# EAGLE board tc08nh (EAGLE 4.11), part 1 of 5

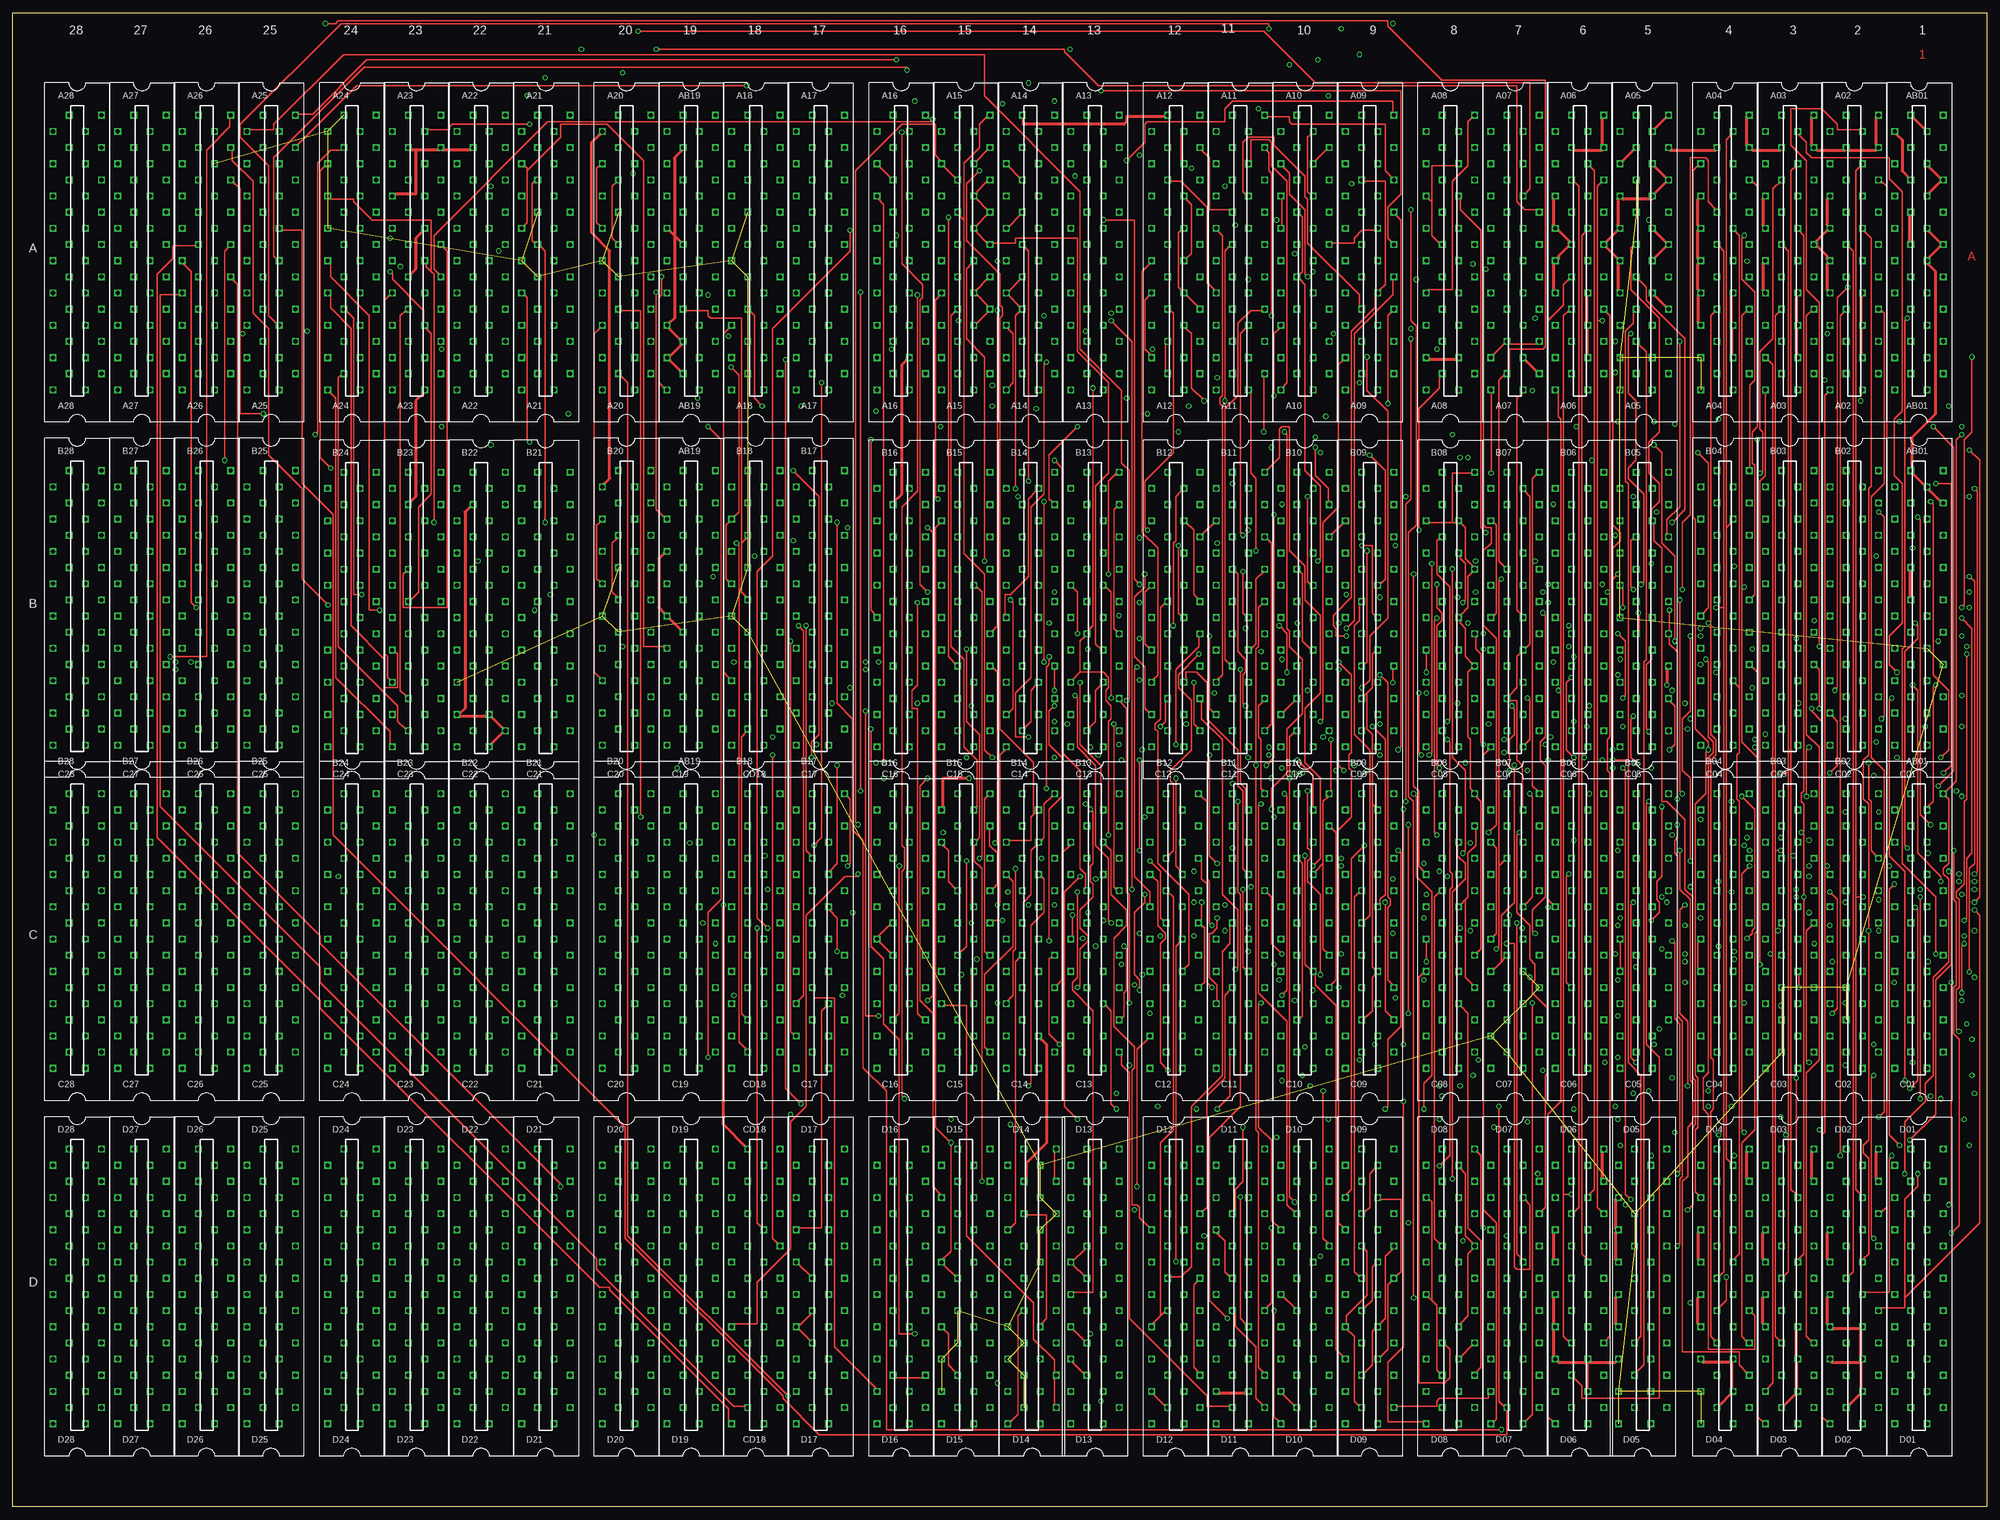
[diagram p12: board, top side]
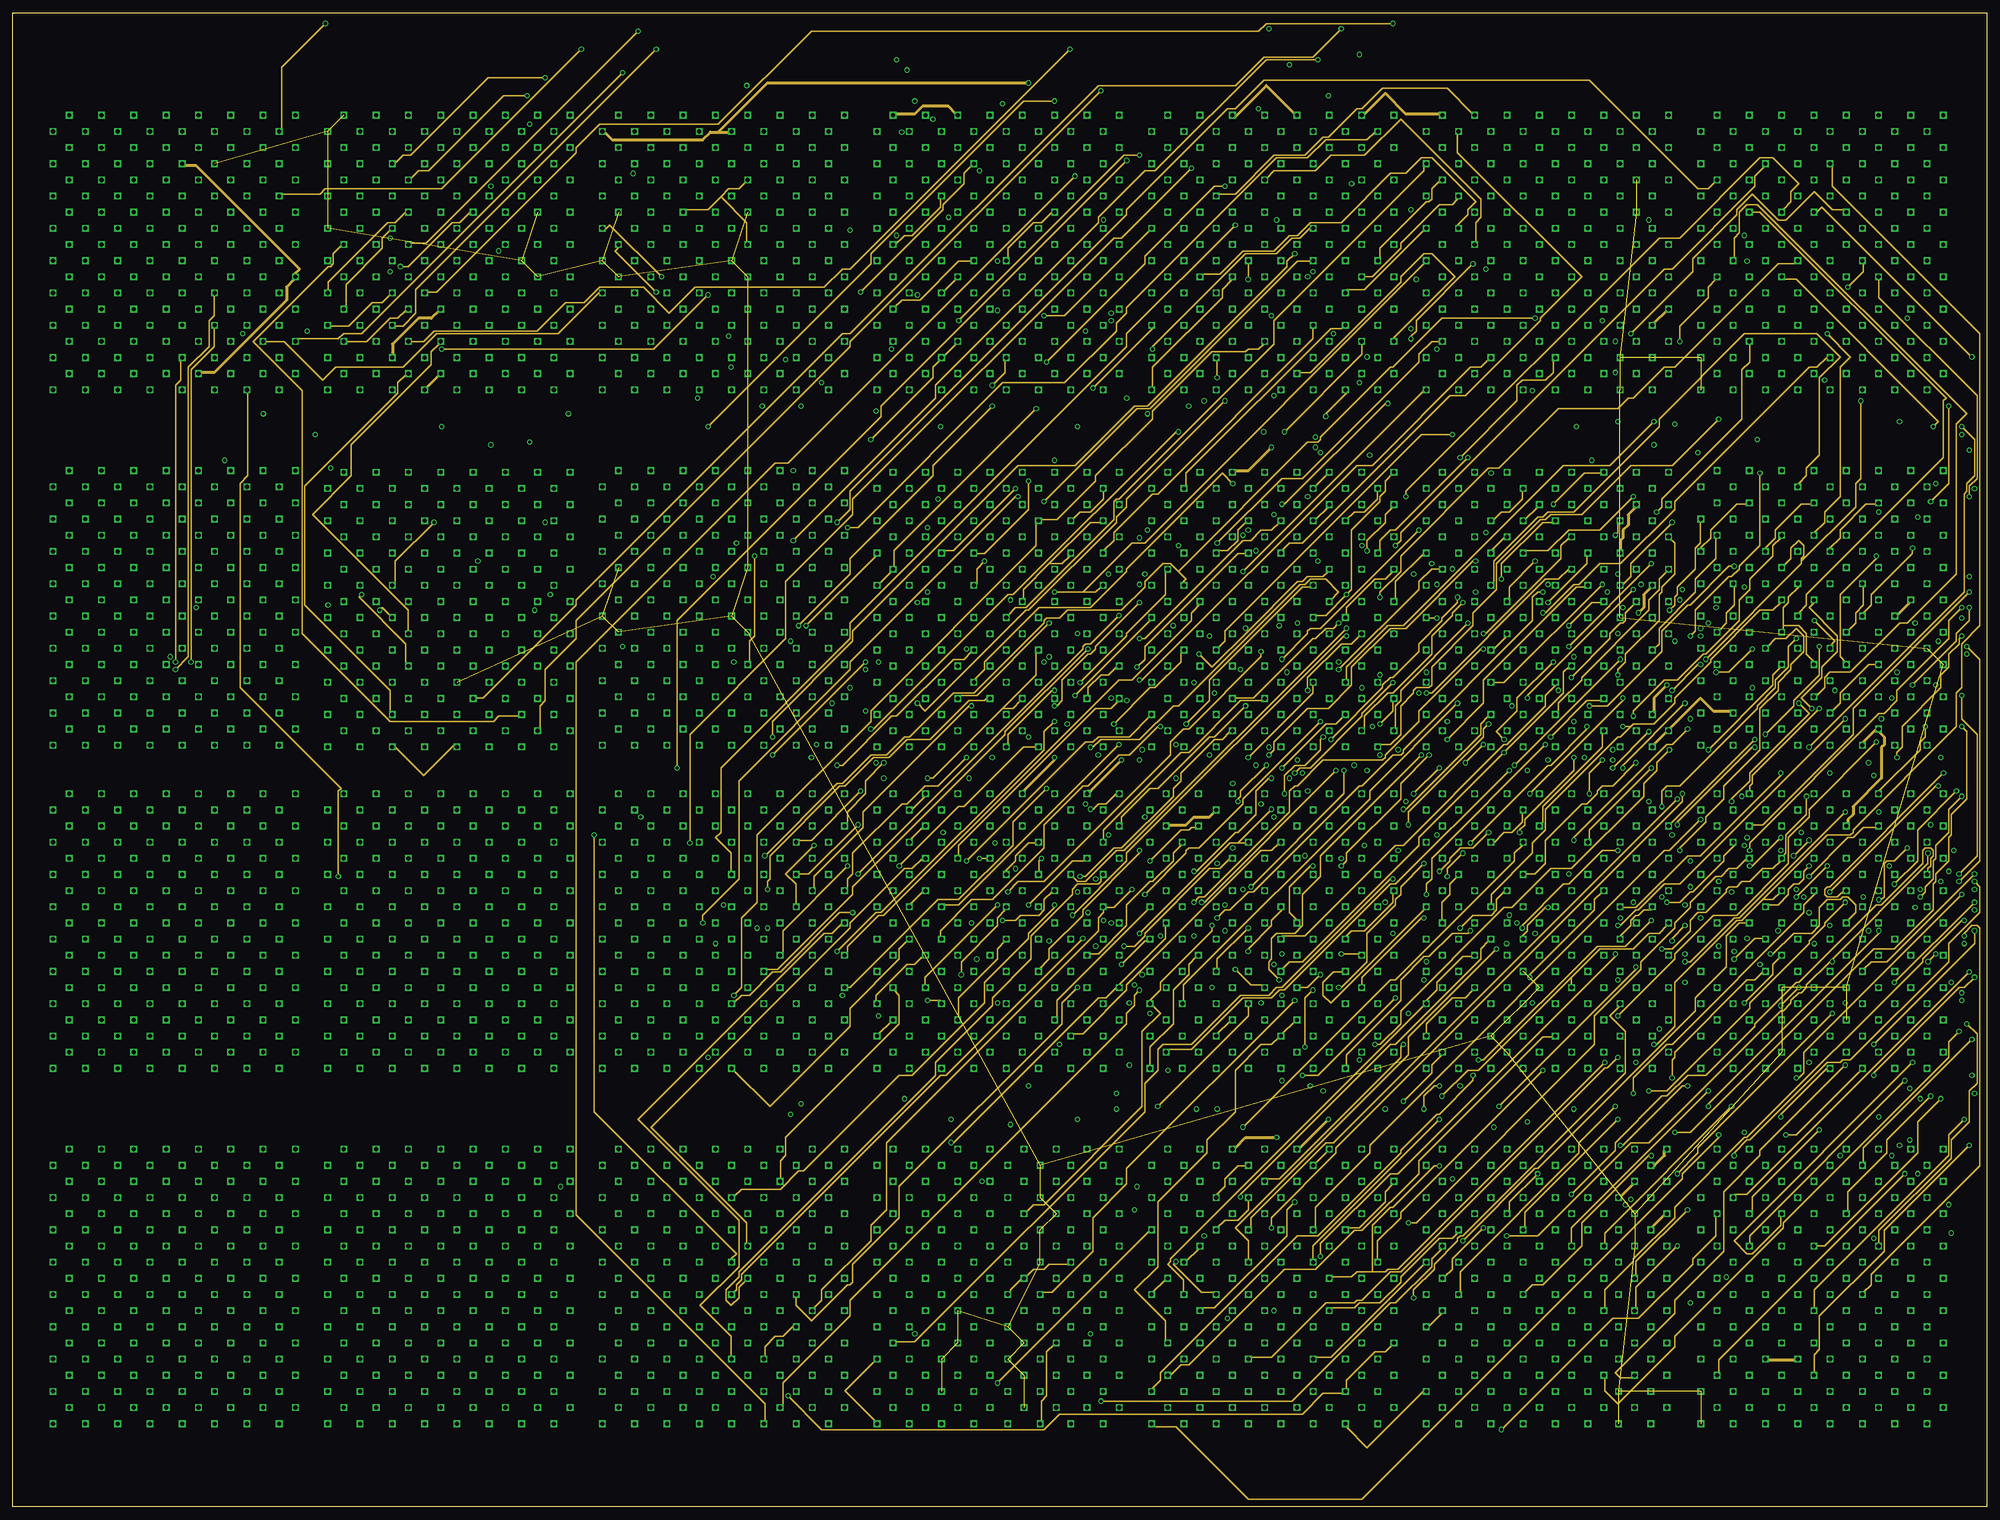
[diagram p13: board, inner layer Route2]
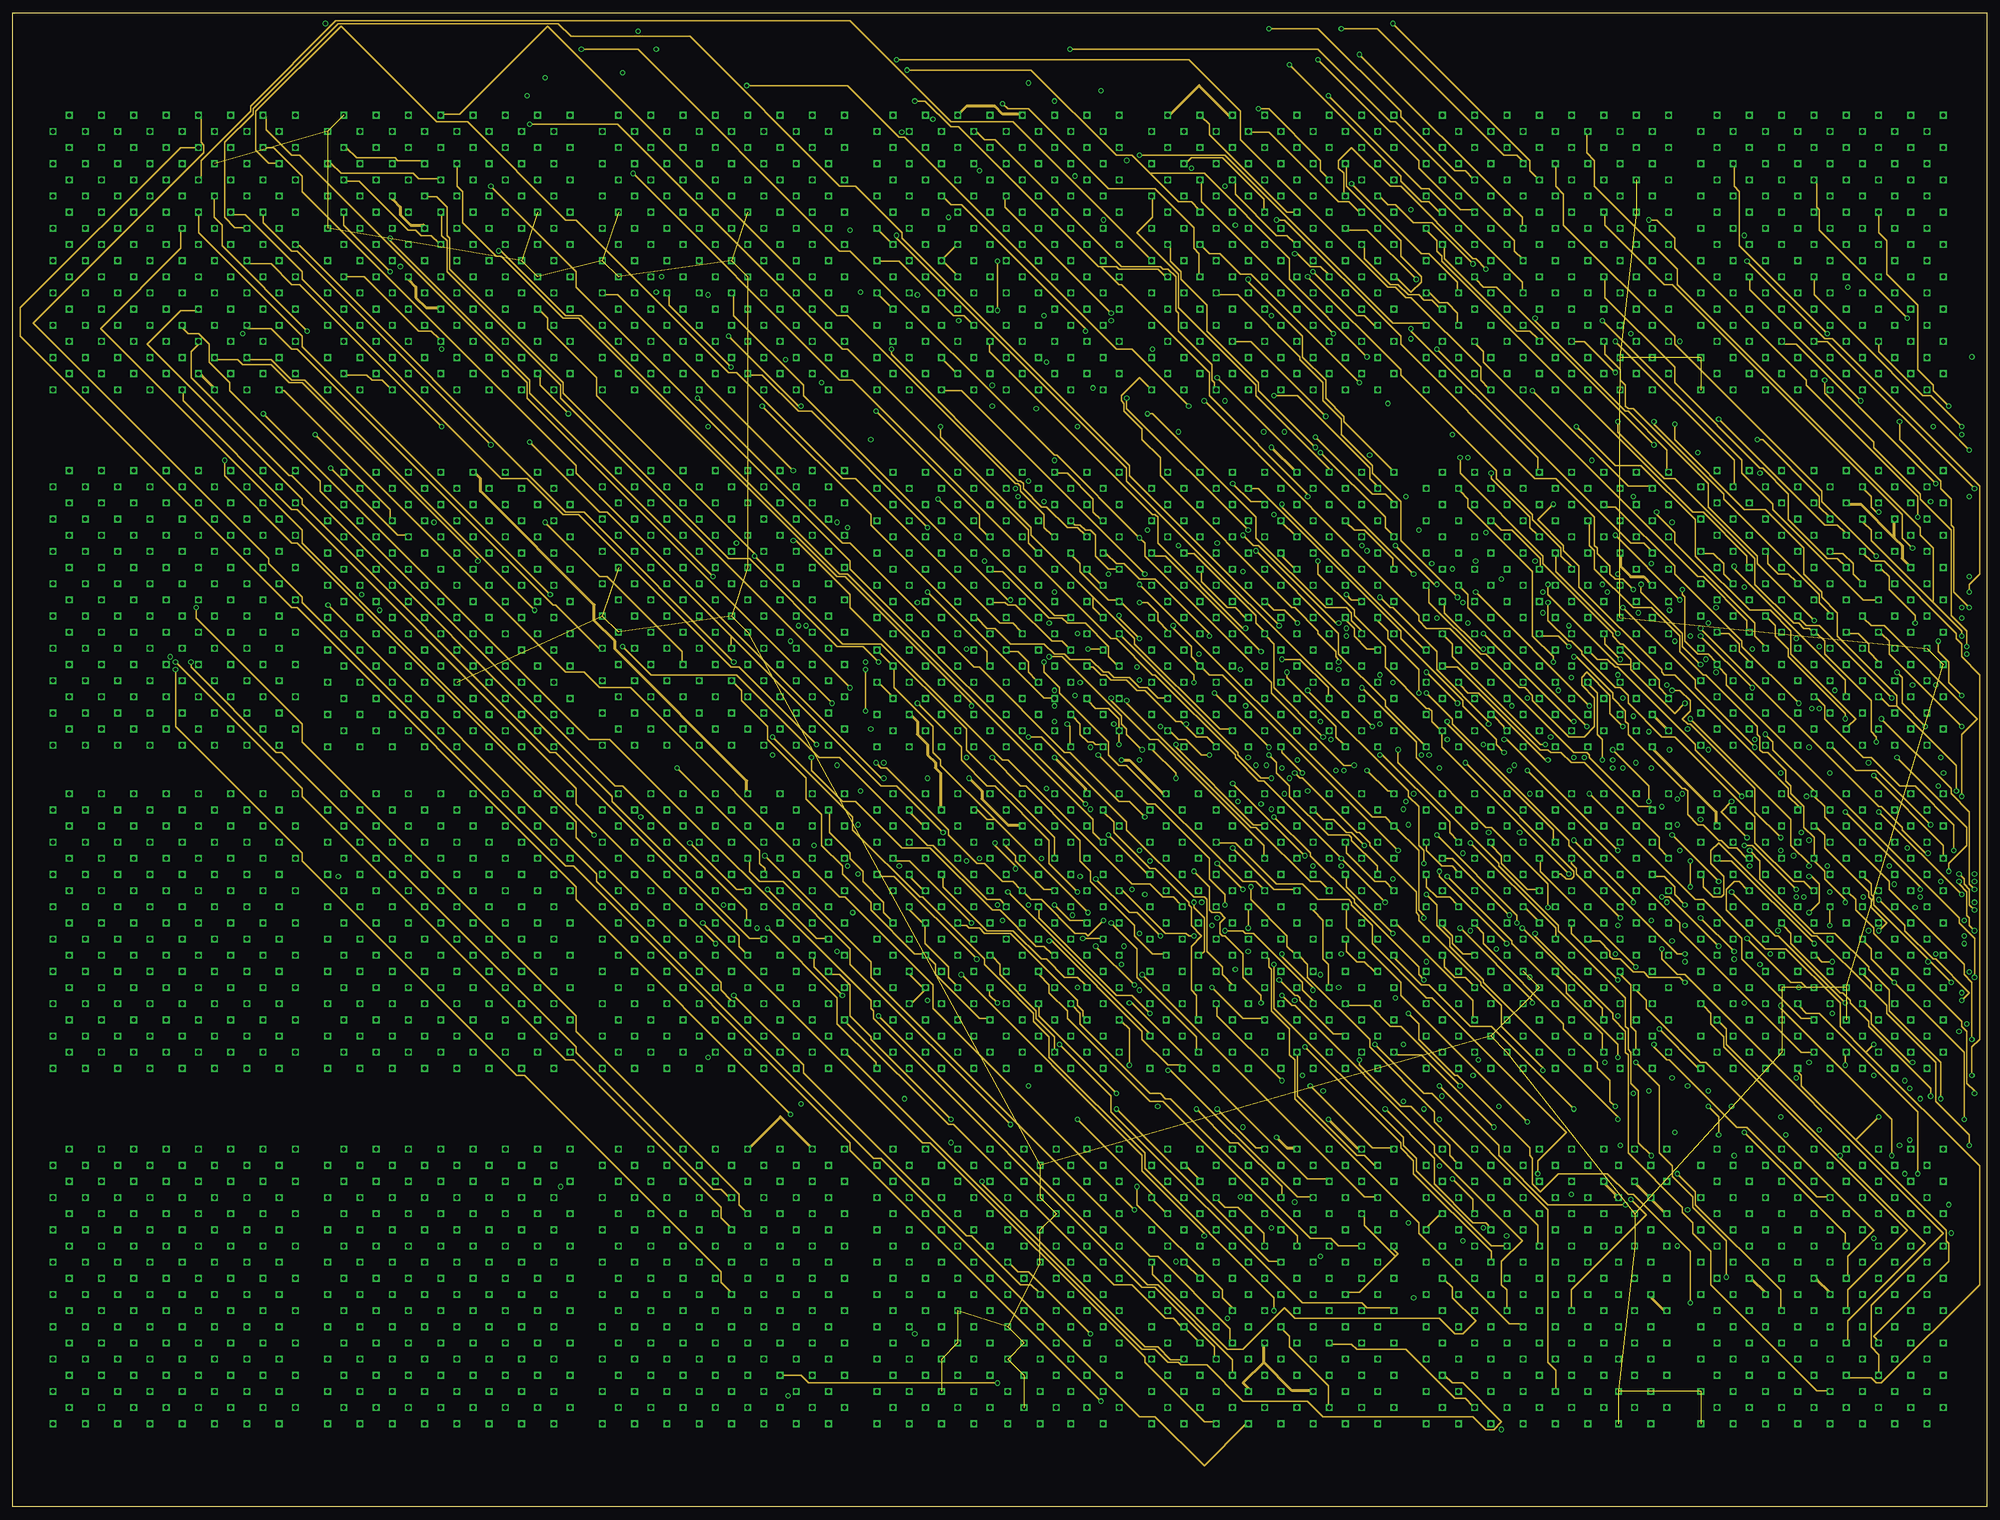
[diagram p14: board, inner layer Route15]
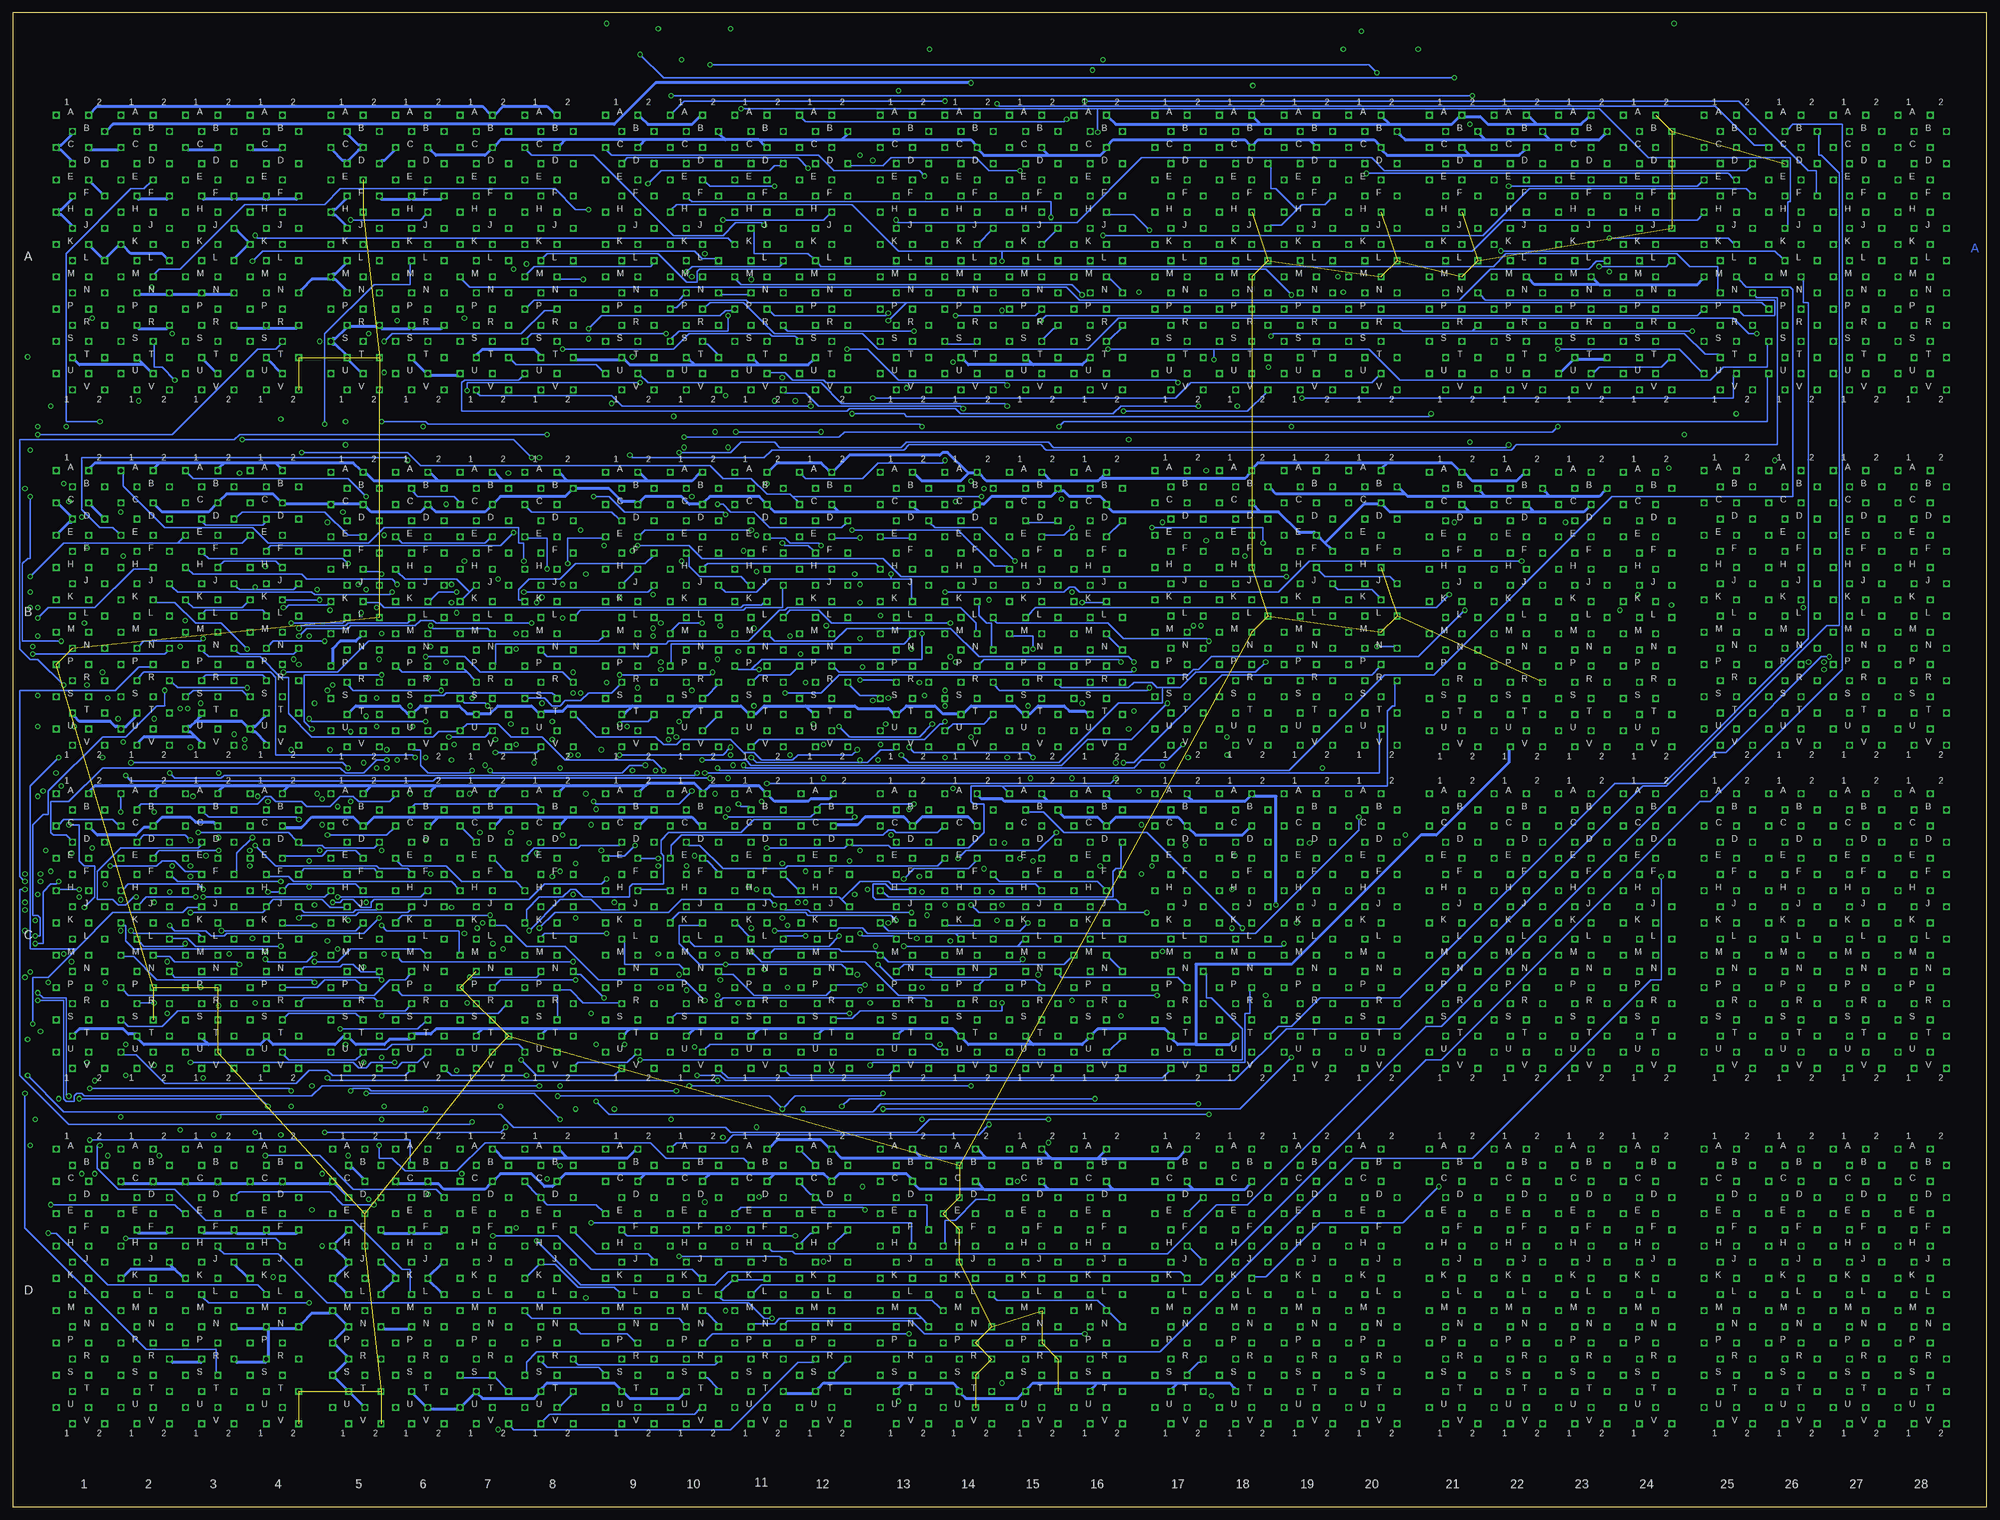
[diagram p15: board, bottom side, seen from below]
Size 387.97 x 293.68 mm. Coordinates in mm from the lower left corner, seen from the top.
Outline: 387.97,0 0,0 0,293.68 387.97,293.68 387.97,0
Copper layers (1*16): Top 0.035mm / dielectric 1.5mm / Bottom 0.035mm
Design rules "10mils": minimum track width 10mil, minimum drill 24mil, track to track 10mil, track to pad 10mil, pad to pad 10mil, via to via 10mil, smd to smd 10mil, copper to edge 40mil, drill to drill 10mil, minimum pad ring 10mil, minimum via ring 8mil, stop-mask expansion 0mil, vias tented up to drill 0mil, thermal gap 10mil
Net classes: 1 Power: width 0.635 mm, drill 0.381 mm, clearance 0.381 mm

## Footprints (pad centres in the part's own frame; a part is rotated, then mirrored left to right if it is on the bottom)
H807 = drill 0.813 square: A1 4.763,28.575; A2 -1.587,28.575; B1 1.587,25.4; B2 -4.763,25.4; C1 4.763,22.225; C2 -1.587,22.225; D1 1.587,19.05; D2 -4.763,19.05; E1 4.763,15.875; E2 -1.587,15.875; F1 1.587,12.7; F2 -4.763,12.7; H1 4.763,9.525; H2 -1.587,9.525; J1 1.587,6.35; J2 -4.763,6.35; K1 4.763,3.175; K2 -1.587,3.175; L1 1.587,0; L2 -4.763,0; M1 4.763,-3.175; M2 -1.587,-3.175; N1 1.587,-6.35; N2 -4.763,-6.35; P1 4.763,-9.525; P2 -1.587,-9.525; R1 1.587,-12.7; R2 -4.763,-12.7; S1 4.763,-15.875; S2 -1.587,-15.875; T1 1.587,-19.05; T2 -4.763,-19.05; U1 4.763,-22.225; U2 -1.587,-22.225; V1 1.587,-25.4; V2 -4.763,-25.4
H807-2 = drill 0.813 square: AA1 4.763,60.325; AA2 -1.587,60.325; AB1 1.587,57.15; AB2 -4.763,57.15; AC1 4.763,53.975; AC2 -1.587,53.975; AD1 1.587,50.8; AD2 -4.763,50.8; AE1 4.763,47.625; AE2 -1.587,47.625; AF1 1.587,44.45; AF2 -4.763,44.45; AH1 4.763,41.275; AH2 -1.587,41.275; AJ1 1.587,38.1; AJ2 -4.763,38.1; AK1 4.763,34.925; AK2 -1.587,34.925; AL1 1.587,31.75; AL2 -4.763,31.75; AM1 4.763,28.575; AM2 -1.587,28.575; AN1 1.587,25.4; AN2 -4.763,25.4; AP1 4.763,22.225; AP2 -1.587,22.225; AR1 1.587,19.05; AR2 -4.763,19.05; AS1 4.763,15.875; AS2 -1.587,15.875; AT1 1.587,12.7; AT2 -4.763,12.7; AU1 4.763,9.525; AU2 -1.587,9.525; AV1 1.587,6.35; AV2 -4.763,6.35; BA1 4.763,-9.525; BA2 -1.587,-9.525; BB1 1.587,-12.7; BB2 -4.763,-12.7; BC1 4.763,-15.875; BC2 -1.587,-15.875; BD1 1.587,-19.05; BD2 -4.763,-19.05; BE1 4.763,-22.225; BE2 -1.587,-22.225; BF1 1.587,-25.4; BF2 -4.763,-25.4; BH1 4.763,-28.575; BH2 -1.587,-28.575; BJ1 1.587,-31.75; BJ2 -4.763,-31.75; BK1 4.763,-34.925; BK2 -1.587,-34.925; BL1 1.587,-38.1; BL2 -4.763,-38.1; BM1 4.763,-41.275; BM2 -1.587,-41.275; BN1 1.587,-44.45; BN2 -4.763,-44.45; BP1 4.763,-47.625; BP2 -1.587,-47.625; BR1 1.587,-50.8; BR2 -4.763,-50.8; BS1 4.763,-53.975; BS2 -1.587,-53.975; BT1 1.587,-57.15; BT2 -4.763,-57.15; BU1 4.763,-60.325; BU2 -1.587,-60.325; BV1 1.587,-63.5; BV2 -4.763,-63.5

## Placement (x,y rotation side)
A02  M903  [H807]  361.94,244.94 0 top
A03  M903  [H807]  349.24,244.94 0 top
A04  M903  [H807]  336.54,244.94 0 top
A05  M903  [H807]  320.66,244.94 0 top
A06  M903  [H807]  307.96,244.94 0 top
A07  A07  [H807]  295.26,244.94 0 top
A08  M206X  [H807]  282.56,244.94 0 top
A09  [H807]  266.69,244.94 0 top
A10  [H807]  253.99,244.94 0 top
A11  A11  [H807]  241.29,244.94 0 top
A12  A12  [H807]  228.59,244.94 0 top
A13  H807  [H807]  212.71,244.94 0 top
A14  [H807]  200.01,244.94 0 top
A15  [H807]  187.31,244.94 0 top
A16  [H807]  174.61,244.94 0 top
A17  H807  [H807]  158.74,244.94 0 top
A18  [H807]  146.04,244.94 0 top
A20  [H807]  120.64,244.94 0 top
A21  [H807]  104.76,244.94 0 top
A22  [H807]  92.06,244.94 0 top
A23  [H807]  79.36,244.94 0 top
A24  W023  [H807]  66.66,244.94 0 top
A25  M916  [H807]  50.78,244.94 0 top
A26  M916  [H807]  38.09,244.94 0 top
A27  H807  [H807]  25.38,244.94 0 top
A28  H807  [H807]  12.68,244.94 0 top
AB01  [H807-2]  374.63,213.19 0 top
AB19  [H807-2]  133.34,213.19 0 top
B02  [H807]  361.94,175.09 0 top
B03  [H807]  349.24,175.09 0 top
B04  [H807]  336.54,175.09 0 top
B05  [H807]  320.66,174.78 0 top
B06  B06  [H807]  307.96,174.78 0 top
B07  B07  [H807]  295.26,174.78 0 top
B08  B08  [H807]  282.56,174.78 0 top
B09  M206X  [H807]  266.69,174.78 0 top
B10  B10  [H807]  253.99,174.78 0 top
B11  [H807]  241.29,174.78 0 top
B12  [H807]  228.59,174.78 0 top
B13  M206X  [H807]  212.71,174.78 0 top
B14  M206X  [H807]  200.01,174.78 0 top
B15  [H807]  187.31,174.78 0 top
B16  [H807]  174.61,174.78 0 top
B17  H807  [H807]  158.74,175.09 0 top
B18  [H807]  146.04,175.09 0 top
B20  [H807]  120.64,175.09 0 top
B21  [H807]  104.76,174.78 0 top
B22  [H807]  92.06,174.78 0 top
B23  [H807]  79.36,174.78 0 top
B24  H807  [H807]  66.66,174.78 0 top
B25  H807  [H807]  50.78,175.09 0 top
B26  H807  [H807]  38.09,175.09 0 top
B27  H807  [H807]  25.38,175.09 0 top
B28  H807  [H807]  12.68,175.09 0 top
C01  C01  [H807]  374.63,111.59 0 top
C02  [H807]  361.94,111.59 0 top
C03  [H807]  349.24,111.59 0 top
C04  C04  [H807]  336.54,111.59 0 top
C05  C05  [H807]  320.66,111.59 0 top
C06  C06  [H807]  307.96,111.59 0 top
C07  B07  [H807]  295.26,111.59 0 top
C08  C08  [H807]  282.56,111.59 0 top
C09  M206X  [H807]  266.69,111.59 0 top
C10  [H807]  253.99,111.59 0 top
C11  [H807]  241.29,111.59 0 top
C12  [H807]  228.27,111.59 0 top
C13  [H807]  212.71,111.59 0 top
C14  M206X  [H807]  200.01,111.59 0 top
C15  [H807]  187.31,111.59 0 top
C16  C16  [H807]  174.61,111.59 0 top
C17  C17  [H807]  158.74,111.59 0 top
C19  H807  [H807]  133.34,111.59 0 top
C20  H807  [H807]  120.64,111.59 0 top
C21  H807  [H807]  104.76,111.59 0 top
C22  H807  [H807]  92.06,111.59 0 top
C23  H807  [H807]  79.36,111.59 0 top
C24  H807  [H807]  66.66,111.59 0 top
C25  H807  [H807]  50.78,111.59 0 top
C26  H807  [H807]  38.09,111.59 0 top
C27  H807  [H807]  25.38,111.59 0 top
C28  H807  [H807]  12.68,111.59 0 top
CD18  [H807-2]  146.04,79.84 0 top
D01  H807  [H807]  374.63,41.74 0 top
D02  M903  [H807]  361.94,41.74 0 top
D03  M903  [H807]  349.24,41.74 0 top
D04  M903  [H807]  336.54,41.74 0 top
D05  M903  [H807]  320.34,41.74 0 top
D06  M903  [H807]  307.96,41.74 0 top
D07  D07  [H807]  295.26,41.74 0 top
D08  [H807]  282.56,41.74 0 top
D09  [H807]  266.69,41.74 0 top
D10  [H807]  253.99,41.74 0 top
D11  M206X  [H807]  241.29,41.74 0 top
D12  D12  [H807]  228.59,41.74 0 top
D13  D13  [H807]  212.71,41.74 0 top
D14  [H807]  200.33,41.74 0 top
D15  [H807]  187.31,41.74 0 top
D16  [H807]  174.61,41.74 0 top
D17  D17  [H807]  158.74,41.74 0 top
D19  H807  [H807]  133.34,41.74 0 top
D20  H807  [H807]  120.64,41.74 0 top
D21  H807  [H807]  104.76,41.74 0 top
D22  H807  [H807]  92.06,41.74 0 top
D23  H807  [H807]  79.36,41.74 0 top
D24  H807  [H807]  66.66,41.74 0 top
D25  H807  [H807]  50.78,41.74 0 top
D26  H807  [H807]  38.09,41.74 0 top
D27  H807  [H807]  25.38,41.74 0 top
D28  H807  [H807]  12.68,41.74 0 top

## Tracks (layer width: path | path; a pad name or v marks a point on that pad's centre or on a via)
00\  (via drill 0.61)
  Route2 0.254: v261.1,290.54 255.51,284.95 245.86,284.95 240.27,279.36 213.35,279.36 164.58,230.59 163.05,230.59 110.73,178.27 110.73,177.25 92.44,158.97 90.92,158.97 B22.S2
  Route15 0.254: v261.1,290.54 268.21,290.54 293.1,265.65 295.64,265.65 296.66,264.63 A07.D1
0_TO_AC\
  Route2 0.254: B06.T2 303.77,155.92 303.77,157.95 308.34,162.52 308.34,163.03 321.55,176.24 321.55,178.27 323.58,180.3 323.58,182.33 325.11,183.86 B05.H1
0_TO_DTB  (via drill 0.61)
  Top 0.254: v175.25,80.23 174.74,80.73 174.74,124.93 175.25,125.44 175.25,129.5 174.74,130.01 174.74,196.56 177.79,199.61 v177.79,238.21
  Route2 0.254: v225.03,78.7 242.81,96.48 242.81,98.51 C11.R1
  Bottom 0.254: v225.03,78.7 223.51,80.23 v175.25,80.23 | v177.79,238.21 179.82,240.25 244.84,240.25 245.86,241.26 A11.M1
0_TO_DTB\  (via drill 0.61)
  Top 0.254: 266.69,144.74 266.69,148.81 263.64,151.85 263.64,173.19 264.65,174.21 264.65,177.76 B09.K2 | 266.69,144.74 266.69,116.29 265.67,115.28 C09.K2 | 266.69,144.74 v266.18,144.74
  Route2 0.254: B10.L1 256.02,175.22 258.05,175.22 v262.11,179.29 263.13,180.3 263.13,191.99 268.72,197.57 268.72,198.59 269.73,199.61 269.73,201.64 271.26,203.16 B09.A1 | v242.81,241.26 242.81,244.31 A11.L1
  Route15 0.254: v266.18,144.74 270.24,140.68 271.26,140.68 C09.A1 | v242.81,241.26 242.81,240.75 253.48,230.09 253.48,226.02 258.05,221.45 258.05,217.89 261.61,214.34 261.61,213.32 271.26,203.67 B09.A1 | v262.11,179.29 263.13,178.27 264.65,178.27 B09.K2
0_TO_EF
  Route15 0.254: A11.E2 240.27,260.57 240.27,258.03 248.4,249.9 250.43,249.9 251.95,248.37 A10.K2
0_TO_EF\
  Top 0.254: A08.N2 278.37,239.23 282.94,239.23 282.94,260.57 285.99,263.61 285.99,272.25 287,273.27 A08.A1
  Route2 0.254: A11.F2 236.71,258.03 240.27,258.03 247.89,265.65 253.99,265.65 257.54,269.2 258.56,269.2 264.15,274.79 265.16,274.79 269.23,278.85 281.93,278.85 287,273.77 A08.A1
  Route15 0.254: A08.R1 283.96,232.63 283.96,234.66 281.93,236.69 280.4,236.69 278.37,238.72 A08.N2
0_TO_LPB\  (via drill 0.61)
  Top 0.254: v289.04,54.83 288.53,55.33 288.53,69.05 287.51,70.07 D08.A1
  Route2 0.254: v289.04,54.83 282.94,48.73 282.94,46.7 281.42,45.17 D08.K2
  Route15 0.254: D12.J2 224.01,47.71 224.01,45.68 238.75,30.95 241.79,30.95 249.92,39.08 251.95,37.05 280.4,37.05 283.45,34 284.97,34 287.51,36.54 282.94,41.11 282.94,43.14 281.42,44.67 D08.K2
0_TO_STA
  Bottom 0.254: A11.N1 243.32,238.21 248.91,238.21 A10.N2
0_TO_STA\  (via drill 0.61)
  Top 0.254: 298.69,185.89 298.69,202.15 299.71,203.16 B07.A1 | 298.69,185.89 298.69,141.69 299.71,140.68 C07.A1 | 298.69,185.89 v299.2,185.89 | B11.P2 239.25,165.57 238.24,166.59 238.24,215.86 240.78,218.4 240.78,232.63 243.32,235.17 245.86,235.17 A11.P1
  Route2 0.254: v299.2,185.89 294.12,180.81 294.12,178.27 B07.K2
  Route15 0.254: v274.81,231.61 274.81,231.1 299.71,206.21 299.71,203.67 B07.A1
  Bottom 0.254: v274.81,231.61 272.27,234.15 248.91,234.15 247.89,235.17 246.37,235.17 A11.P1
0_TO_STATE\
  Route2 0.254: CD18.AV2 141.72,85.81 148.83,78.7 164.58,94.45 164.58,98.01 174.23,107.66 174.23,109.69 175.75,111.21 C16.L1
0_TO_W\
  Route2 0.254: CD18.BH2 144.26,51.78 144.26,55.84 125.46,74.64 164.58,113.75 164.58,114.77 175.25,125.44 176.77,125.44 178.8,127.47 C16.E1
01\  (via drill 0.61)
  Route2 0.254: v271.26,291.55 246.37,291.55 244.84,290.03 156.96,290.03 138.67,271.74 115.3,271.74 110.73,267.17 110.73,266.15 83.3,238.72 81.27,238.72 A23.N1
  Route15 0.254: v271.26,291.55 298.18,264.63 298.18,262.6 299.71,261.07 A07.E1
1_TO_DF  (via drill 0.61)
  Top 0.254: C12.J1 229.6,117.31 229.6,112.23 C12.L1 229.6,111.21 228.59,110.2 v228.59,48.22
  Route2 0.254: v228.59,48.22 228.08,47.71 233.67,42.13 236.21,42.13 D11.L2 | v256.53,284.44 246.37,284.44 224.52,262.6 222.49,262.6 213.35,253.45 213.35,252.44 181.34,220.43 181.34,217.89 v153.4,189.95
  Route15 0.254: v256.53,284.44 276.34,264.63 276.34,263.11 284.47,254.98 287,254.98 A08.H1 | v153.4,189.95 153.91,189.95 164.58,179.29 164.58,176.75 194.55,146.77 195.57,146.77 219.95,122.39 223.51,122.39 226.05,119.85 228.08,119.85 229.6,118.33 C12.J1
1_TO_DTF  (via drill 0.61)
  Top 0.254: v170.17,96.48 167.62,96.48 v167.62,156.43
  Route15 0.254: v170.17,96.48 223,43.65 225.03,43.65 239.76,28.92 239.76,26.38 D11.S2 | v167.62,156.43 v167.62,164.55
  Bottom 0.254: v167.62,164.55 168.13,164.05 225.54,164.05 226.55,165.06 B12.P2
02\  (via drill 0.61)
  Route2 0.254: v104.63,280.89 93.46,280.89 78.22,265.65 76.69,265.65 75.17,264.12 A23.D2
  Route15 0.254: v264.65,285.46 296.66,253.45 296.66,251.93 A07.J1
  Bottom 0.254: v264.65,285.46 260.08,280.89 v104.63,280.89
03\  (via drill 0.61)
  Route2 0.254: v101.08,277.33 96.5,277.33 81.77,262.6 79.74,262.6 78.22,261.07 A23.E2
  Route15 0.254: v258.56,277.33 276.85,259.04 278.37,259.04 296.66,240.75 296.66,239.23 A07.N1
  Bottom 0.254: v258.56,277.33 v101.08,277.33
04\  (via drill 0.61)
  Top 0.254: v122.92,290.03 245.86,290.03 256.02,279.87 298.18,279.87 298.18,259.04 297.17,258.03 A07.F1
  Route2 0.254: v122.92,290.03 81.27,248.37 78.22,248.37 A23.K2
05\
  Bottom 0.254: A07.M1 299.71,241.26 298.18,239.74 180.83,239.74 178.29,237.2 103.62,237.2 97.52,243.29 78.22,243.29 76.69,244.82 75.17,244.82 A23.L2
06\  (via drill 0.61)
  Top 0.254: v126.48,286.47 206.74,286.47 206.74,285.97 213.35,279.36 295.64,279.36 295.64,256.5 297.17,254.98 299.71,254.98 A07.H1
  Route2 0.254: v126.48,286.47 79.23,239.23 79.23,234.66 76.69,232.12 75.17,232.12 A23.R2
07\  (via drill 0.61)
  Route2 0.254: v207.76,286.47 164.58,243.29 163.05,243.29 159.5,239.74 134.1,239.74 129.02,234.66 123.94,239.74 115.3,239.74 112.25,236.69 108.7,236.69 103.11,231.1 82.79,231.1 80.76,229.07 78.22,229.07 A23.S2
  Route15 0.254: v207.76,286.47 256.53,286.47 270.75,272.25 271.76,272.25 295.13,248.88 295.13,246.85 296.66,245.33 A07.L1
76  (via drill 0.61)
  Route15 0.254: v323.58,93.94 331.2,86.32 C04.V2
  Bottom 0.254: v323.58,93.94 308.34,93.94 306.82,95.47 C06.S2
76+77  (via drill 0.61)
  Route2 0.254: v335.26,73.11 335.26,72.61 328.15,65.49 328.15,64.48 265.16,1.49 242.81,1.49 228.59,15.71 224.01,15.71 D12.V2 | v333.23,78.7 333.23,79.21 366.76,112.74 v366.76,113.25
  Route15 0.254: v335.26,73.11 335.26,76.67 v333.23,78.7 | v366.76,113.25 368.29,114.77 365.24,117.82 365.24,119.34 364.73,119.85 364.73,120.87 356.09,129.5 356.09,132.04 354.57,133.57 C03.C1
76\
  Route2 0.254: C06.T2 302.75,92.42 300.72,92.42 276.34,68.03 276.34,65.49 265.16,54.32 263.64,54.32 256.02,46.7 249.92,46.7 231.12,27.9 229.6,27.9 227.57,25.87 D12.S2
  Bottom 0.254: D12.S2 226.55,26.38 224.52,28.41 224.01,28.41 D12.R2
77
  Bottom 0.254: C06.U2 306.82,88.86 308.34,87.34 311.39,87.34 312.41,86.32 315.45,86.32 C05.V2
77\  (via drill 0.61)
  Top 0.254: D12.T2 224.01,22.31 226.55,19.77 D12.U2
  Route2 0.254: v287,84.8 287,83.78 280.4,77.18 279.89,77.18 272.78,70.07 272.78,69.56 256.53,53.3 252.46,53.3 225.54,26.38 225.54,24.85 224.01,23.33 D12.T2
  Bottom 0.254: v287,84.8 301.74,84.8 302.75,85.81 C06.V2
+3V@A09U1  (via drill 0.61)
  Top 0.254: 278.88,256.5 278.88,249.9 280.4,248.37 A08.K2 | 278.88,256.5 278.37,257.01 A08.F2 | 278.88,256.5 278.88,263.61 283.96,263.61 A08.D1 | B13.U2 211.31,152.87 212.84,154.39 212.84,160.49 213.85,161.51 B13.R1 | A07.T2 291.07,226.53 293.1,228.56 A07.S2 294.12,228.56 299.71,228.56 A07.S1
  Route2 0.254: v221.47,162.52 221.98,162.52 264.15,204.69 267.19,204.69 286.5,223.99 288.53,223.99 290.05,225.51 A07.T2
  Route15 0.254: A08.K2 281.42,247.87 281.42,245.33 295.64,231.1 298.18,231.1 299.71,229.58 A07.S1
  Bottom 0.254: A09.U1 271.76,222.97 273.29,224.5 289.04,224.5 290.05,225.51 A07.T2 | v221.47,162.52 214.87,162.52 B13.R1
+3V@B12U1  (via drill 0.61)
  Top 0.254: B14.U2 198.61,152.87 200.14,154.39 200.14,160.49 201.15,161.51 B14.R1 | v232.14,162.01 232.14,153.89 233.16,152.87 B12.U1
  Route2 0.254: 203.69,185.38 198.61,180.3 198.61,178.27 B14.K2 | 203.69,185.38 206.23,185.38 207.76,186.91 B13.F2 | 203.69,185.38 211.82,193.51 213.85,193.51 B13.D1
  Route15 0.254: B14.N2 195.57,168.11 197.6,168.11 199.63,166.08 199.63,164.05 201.15,162.52 B14.R1 | B13.F2 208.27,186.91 209.79,185.38 209.79,183.86 215.38,178.27 216.9,178.27 B13.K1 217.92,177.76 232.14,163.54 v232.14,162.01 | B14.A1 205.22,203.16 207.25,203.16 212.33,198.08 212.33,195.54 213.85,194.02 B13.D1
  Bottom 0.254: B14.N2 195.57,168.62 195.57,173.7 196.58,173.7 198.11,175.22 198.11,177.76 B14.K2
+3V@C08U1  (via drill 0.61)
  Top 0.254: C04.N2 331.2,105.63 331.2,111.21 C04.L2 | C05.N2 315.96,105.63 315.96,111.21 C05.L2
  Route2 0.254: C05.J1 322.06,117.31 320.53,117.31 319.52,116.29 319.01,116.29 317.99,115.28 317.99,114.26 315.96,112.23 C05.L2 | v353.05,123.91 360.67,131.53 361.68,131.53 363.71,133.57 366.25,133.57 C02.C1
  Route15 0.254: v353.05,123.91 353.55,123.91 355.08,122.39 355.08,118.83 v353.05,116.8 | C05.U2 319.01,89.88 319.01,93.43 317.99,94.45 317.99,102.58 315.96,104.61 C05.N2
  Bottom 0.254: C08.U1 287.51,89.88 288.53,90.89 313.42,90.89 314.44,89.88 318.5,89.88 C05.U2 319.52,88.86 320.53,87.85 333.74,87.85 334.76,88.86 C04.U2 | C02.C1 367.27,134.07 368.29,135.09 377.94,135.09 378.95,134.07 C01.C1 | C05.J1 322.56,117.82 325.61,117.82 327.14,119.34 336.79,119.34 337.81,118.33 C04.J1 338.31,117.31 338.82,116.8 v353.05,116.8 | C04.N2 331.2,105.63 330.69,106.13 323.58,106.13 323.07,106.64 321.04,106.64 319.52,105.12 316.47,105.12 C05.N2
+3V@C15U1
  Top 0.254: C15.U1 191.5,89.88 190.99,90.39 190.99,104.61 196.58,110.2 196.58,122.9 195.57,123.91 C14.F2 | C14.A1 204.2,139.66 202.68,138.14 202.68,131.53 202.17,131.03 C14.D1 201.15,130.01 200.14,128.99 200.14,120.36 198.61,118.83 198.61,115.28 C14.K2
  Route2 0.254: C14.D1 201.15,130.52 199.63,130.52 197.09,127.98 197.09,126.96 195.06,124.93 C14.F2
  Bottom 0.254: C14.K2 198.61,114.26 204.2,114.26 C14.K1 | C16.H2 173.21,121.37 174.74,122.9 194.04,122.9 195.06,123.91 C14.F2
+3V@D09U1
  Top 0.254: D09.U1 271.76,19.77 279.89,19.77 279.89,20.79 280.4,21.3 290.05,21.3 290.05,22.31 D07.T2
  Bottom 0.254: D07.T2 291.07,23.33 293.1,25.36 D07.S2 294.12,25.36 299.71,25.36 D07.S1
+3V@D10U1
  Top 0.254: D11.F2 236.71,53.81 238.24,52.29 238.24,46.19 239.25,45.17 D11.K2 | D10.M2 251.95,39.08 249.41,41.62 D10.L2
  Route2 0.254: D11.D1 242.81,60.41 242.81,58.38 240.78,56.35 238.24,56.35 236.71,54.83 D11.F2
  Route15 0.254: D10.U1 258.56,19.77 258.56,23.84 250.94,31.46 250.94,33.49 249.41,35.01 D10.N2
  Bottom 0.254: D10.N2 249.41,36.03 251.45,38.06 251.95,38.06 D10.M2 | D11.K2 240.27,44.67 245.86,44.67 D11.K1 246.37,44.67 248.91,42.13 D10.L2 248.91,41.11 248.4,40.6 207.25,40.6 205.73,39.08 D14.M1
-15V  (via drill 0.61)
  Top 0.635: AB01.AB2 370.32,269.71 371.33,268.69 371.33,262.6 372.86,261.07 AB01.AE2 | B20.B2 116.32,201.13 117.33,202.15 117.33,246.85 113.78,250.41 113.78,268.19 115.3,269.71 A20.B2
  Route2 0.635: 138.67,270.22 137.15,270.22 135.62,268.69 117.84,268.69 116.32,270.22 A20.B2 | 138.67,270.22 140.7,270.22 A18.B2 | v199.63,279.87 148.32,279.87 138.67,270.22
  Bottom 0.635: 85.84,198.59 76.19,198.59 75.17,199.61 B23.B2 | 85.84,198.59 86.85,199.61 B22.B2 | 98.54,198.59 99.55,199.61 B21.B2 | 85.84,198.59 98.54,198.59 | 114.28,199.1 113.78,198.59 98.54,198.59 | 114.28,199.1 115.3,200.11 B20.B2 | 114.28,199.1 139.69,199.1 140.7,200.11 B18.B2 | AB01.AF2 370.32,258.03 372.86,260.57 AB01.AE2 | 85.84,268.69 76.19,268.69 75.17,269.71 A23.B2 | 85.84,268.69 86.85,269.71 A22.B2 | 98.54,268.69 99.55,269.71 A21.B2 | 98.54,268.69 85.84,268.69 | 98.54,268.69 114.28,268.69 115.3,269.71 A20.B2 | v199.63,279.87 261.61,279.87 269.73,271.74 368.29,271.74 369.3,270.73 AB01.AB2
ADDR_ACC  (via drill 0.61)
  Route2 0.254: v347.46,76.67 347.46,77.18 356.6,86.32 C02.V2
  Route15 0.254: v184.39,76.16 168.64,91.91 168.64,92.42 164.58,96.48 164.58,102.58 162.55,104.61 160.51,104.61 C17.N1
  Bottom 0.254: v184.39,76.16 207.76,76.16 210.3,73.62 246.87,73.62 247.89,74.64 289.55,74.64 292.09,77.18 346.95,77.18 v347.46,76.67
ADDR_ACC\  (via drill 0.61)
  Top 0.254: v203.19,141.19 203.19,165.06 203.69,165.57 v203.69,167.09
  Route2 0.254: v203.19,141.19 196.58,134.58 196.58,130.01 185.91,119.34 181.85,119.34 164.58,102.07 164.07,102.07 C17.P1
  Route15 0.254: v203.69,167.09 206.23,167.09 217.92,155.41 217.92,153.89 218.93,152.87 218.93,151.85 v221.98,148.81
  Bottom 0.254: v221.98,148.81 223,147.79 233.67,147.79 234.68,146.77 240.78,146.77 242.3,148.3 244.33,148.3 246.87,150.84 256.53,150.84 257.54,149.82 260.08,149.82 261.61,151.35 273.29,151.35 277.35,155.41 B08.T2
B-BRK  (via drill 0.61)
  Top 0.254: v251.95,59.91 250.94,60.92 v250.94,143.22 250.94,151.35 251.95,152.36 B10.U2 | B10.S2 251.95,158.46 249.41,155.92 B10.T2
  Route2 0.254: v251.95,59.91 250.43,58.38 250.43,53.3 236.21,39.08 233.67,39.08 D12.M1
  Route15 0.254: v365.75,143.73 379.46,130.01 379.46,127.98 C01.E1
  Bottom 0.254: B10.R2 249.41,161.51 251.45,159.47 251.95,159.47 B10.S2 | v365.75,143.73 364.73,142.71 305.29,142.71 304.79,143.22 v250.94,143.22 | B10.T2 249.41,155.41 251.95,152.87 B10.U2
B-BRK\  (via drill 0.61)
  Top 0.254: v357.11,144.23 358.63,145.76 358.63,154.39 357.62,155.41 B02.T2
  Route2 0.254: B02.J1 363.71,180.81 363.71,177.25 362.19,175.73 362.19,173.7 360.67,172.17 B02.M2 | B02.C1 366.25,197.07 364.22,197.07 359.14,191.99 359.14,190.46 357.11,188.43 B02.F2 | B02.P1 366.25,165.57 364.73,165.57 359.14,159.98 359.14,157.95 357.62,156.43 B02.T2
  Route15 0.254: B02.M2 360.67,171.67 362.7,171.67 364.73,169.63 364.73,168.11 366.76,166.08 B02.P1 | B02.F2 357.62,187.41 359.65,187.41 361.68,185.38 361.68,183.35 363.21,181.83 B02.J1 | v253.48,144.23 249.41,148.3 249.41,148.81 B10.V2
  Bottom 0.254: v253.48,144.23 253.99,143.73 346.44,143.73 346.95,143.22 356.09,143.22 v357.11,144.23
B-RUN  (via drill 0.61)
  Top 0.254: v377.94,161.51 377.43,161 377.43,138.65 376.41,137.63 C01.B1
  Route2 0.254: v282.94,210.78 276.85,210.78 238.24,172.17 238.24,170.14 236.71,168.62 B11.N2
  Bottom 0.254: v377.94,161.51 383.02,166.59 384.54,166.59 386.57,168.62 386.57,209.77 344.41,209.77 343.39,210.78 v282.94,210.78
B-XSTA  (via drill 0.61)
  Top 0.254: D12.E1 233.67,57.87 234.68,58.89 234.68,80.73 238.24,84.29 238.24,100.55 239.25,101.56 C11.P2 | v203.19,225.01 202.68,224.5 202.68,199.1 200.14,196.56 200.14,163.03 197.09,159.98 197.09,151.35 v199.63,151.35
  Route2 0.254: v238.24,259.55 236.21,259.55 222.49,245.83 222.49,244.31 v203.19,225.01
  Route15 0.254: v199.63,151.35 202.17,151.35 218.93,134.58 218.93,133.06 232.14,119.85 234.17,119.85 234.68,119.34 234.68,109.18 237.73,106.13 237.73,104.61 239.76,102.58 C11.P2
  Bottom 0.254: v238.24,259.55 250.94,259.55 251.95,260.57 A10.E2
BAC_00
  Route2 0.254: B07.D1 297.17,194.02 299.71,196.56 B07.C1
  Bottom 0.254: B06.B1 309.36,199.61 308.34,198.59 301.23,198.59 300.21,197.57 B07.C1
BAC_00\  (via drill 0.61)
  Route2 0.254: v331.71,135.09 325.61,128.99 324.6,128.99 266.69,71.08 266.69,69.56 256.02,58.89 256.02,54.83 D10.F1 | v302.75,197.07 308.85,203.16 312.41,203.16 B06.A1
  Route15 0.254: v302.75,197.07 299.71,194.02 304.79,188.94 304.79,187.92 307.83,184.87 307.83,180.81 324.09,164.55 324.09,164.05 324.6,163.54 326.63,163.54 348.98,141.19 348.98,139.66 351.01,137.63 C03.B1
  Bottom 0.254: v331.71,135.09 332.22,135.6 349.49,135.6 350.5,136.61 C03.B1
BAC_01
  Route2 0.254: B07.F2 290.56,187.92 293.1,190.46 B07.E2
  Bottom 0.254: B06.E1 312.41,190.46 311.39,189.45 295.13,189.45 294.12,190.46 B07.E2
BAC_01\  (via drill 0.61)
  Top 0.254: v257.54,81.75 257.54,52.79 258.56,51.78 D10.H1
  Route2 0.254: v321.55,81.75 325.11,81.75 341.36,98.01 341.36,99.02 353.05,110.71 353.05,111.21 356.09,114.26 356.09,114.77 v360.16,118.83
  Route15 0.254: v360.16,118.83 360.16,119.34 356.09,123.41 356.09,124.93 354.06,126.96 C03.E1 354.06,127.98 354.06,131.53 352.03,133.57 352.03,137.63 349.49,140.17 349.49,141.69 348.47,142.71 348.47,144.74 344.92,148.3 343.9,148.3 343.39,148.81 343.39,151.35 342.88,151.85 342.88,153.38 332.73,163.54 332.22,163.54 327.65,168.11 327.65,171.16 322.06,176.75 318.5,176.75 310.88,184.37 310.88,187.92 309.87,188.94 309.87,193.51 B06.D1
  Bottom 0.254: v257.54,81.75 317.49,81.75 317.99,82.26 321.04,82.26 v321.55,81.75
BAC_02
  Bottom 0.254: 298.18,179.79 299.71,178.27 B07.K1 | 298.18,179.79 297.17,180.81 B07.J1 | 298.18,179.79 300.72,182.33 310.88,182.33 312.41,183.86 B06.H1
BAC_02\  (via drill 0.61)
  Route2 0.254: v280.4,76.16 255.51,51.27 255.51,48.73 D10.J1 | v318.5,81.24 318.5,84.29 325.11,90.89 326.12,90.89 352.03,116.8 352.03,118.33 354.57,120.87 C03.H1 | v301.74,177.76 309.36,185.38 309.36,186.91 B06.F1
  Route15 0.254: v301.74,177.76 301.74,174.21 305.8,170.14 306.31,170.14 308.34,168.11 308.34,167.6 314.94,161 315.96,161 317.49,159.47 317.49,157.95 324.09,151.35 326.63,151.35 342.38,135.6 342.38,130.52 350,122.9 352.03,122.9 353.55,121.37 C03.H1
  Bottom 0.254: v280.4,76.16 285.48,81.24 v318.5,81.24
BAC_03  (via drill 0.61)
  Route2 0.254: B07.N2 291.07,168.62 293.61,171.16 B07.M2 | v305.8,173.19 310.37,177.76 312.41,177.76 B06.K1
  Bottom 0.254: v305.8,173.19 305.29,172.68 294.62,172.68 294.12,172.17 B07.M2
BAC_03\  (via drill 0.61)
  Top 0.254: v353.05,87.34 352.54,87.85 352.54,113.25 353.55,114.26 C03.K1 | v281.93,150.84 282.43,150.33 282.43,124.93 282.94,124.42 282.94,121.88 282.43,121.37 282.43,69.05 v280.4,67.02
  Route2 0.254: 267.19,46.19 269.73,46.19 270.24,46.7 272.27,46.7 v312.91,87.34 | 267.19,46.19 264.15,46.19 263.13,45.17 259.06,45.17 D10.K1 | v281.93,150.84 289.04,157.95 289.04,162.52 307.32,180.81 309.36,180.81 B06.J1 | v280.4,67.02 279.38,67.02 271.26,58.89 270.75,58.89 267.19,55.33 267.19,46.19
  Bottom 0.254: v312.91,87.34 317.49,87.34 318.5,86.32 320.03,86.32 321.04,87.34 v353.05,87.34
BAC_04  (via drill 0.61)
  Top 0.254: 292.59,107.15 293.1,107.66 293.1,108.17 C07.M2 | 292.59,107.15 291.07,105.63 C07.N2 | v295.13,145.76 295.13,118.83 292.59,116.29 292.59,107.15
  Route2 0.254: v295.13,145.76 v315.96,166.59
  Route15 0.254: v315.96,166.59 312.91,169.63 312.91,171.16 B06.M1
BAC_04\  (via drill 0.61)
  Route2 0.254: v293.61,53.3 299.71,53.3 317.99,71.59 321.55,71.59 347.46,97.5 347.97,97.5 349.49,99.02 349.49,99.53 351.01,101.05 351.52,101.05 352.54,102.07 352.54,102.58 357.11,107.15 | 357.11,107.15 v357.62,107.15 | v376.41,128.49 376.41,126.45 357.11,107.15
  Route15 0.254: v357.62,107.15 355.59,107.15 354.57,108.17 C03.M1 | v331.71,172.68 366.76,137.63 367.27,137.63 371.33,133.57 371.33,133.06 375.91,128.49 v376.41,128.49
  Bottom 0.254: v293.61,53.3 280.91,53.3 274.31,46.7 254.49,46.7 252.97,45.17 D10.K2 | v331.71,172.68 331.2,173.19 322.56,173.19 322.06,173.7 310.37,173.7 309.87,174.21 B06.L1
BAC_05
  Bottom 0.254: 298.69,164.05 299.71,165.06 B07.P1 | 298.69,164.05 297.17,162.52 B07.R1 | 298.69,164.05 311.39,164.05 312.41,165.06 B06.P1
BAC_05\  (via drill 0.61)
  Top 0.254: v340.85,111.72 341.87,112.74 341.87,113.25 342.38,113.75 342.38,137.12 v339.84,139.66
  Route15 0.254: v340.85,111.72 349.49,103.09 351.52,103.09 352.54,102.07 353.55,102.07 C03.P1 | v339.84,139.66 330.69,148.81 330.69,149.82 315.45,165.06 314.94,165.06 313.42,166.59 311.39,166.59 309.87,168.11 B06.N1
BAC_06  (via drill 0.61)
  Top 0.254: v273.29,90.89 v273.29,137.12
  Route2 0.254: v273.29,90.89 272.78,90.39 272.78,88.35 248.91,64.48 246.37,64.48 D11.C1 | v273.29,137.12 273.8,137.12 288.53,151.85 288.53,153.89 290.05,155.41 B07.T2 | v302.25,151.35 309.36,158.46 312.41,158.46 B06.S1
  Route15 0.254: B07.U2 293.1,152.87 293.1,153.38 291.07,155.41 B07.T2
  Bottom 0.254: v302.25,151.35 295.13,151.35 294.12,152.36 B07.U2
BAC_06\  (via drill 0.61)
  Route2 0.254: v309.87,140.17 309.87,144.23 v312.41,146.77
  Route15 0.254: v309.87,140.17 330.69,119.34 332.22,119.34 339.84,111.72 339.84,107.66 351.52,95.97 353.55,95.97 C03.S1 | v312.41,146.77 312.41,150.84 311.39,151.85 311.39,159.98 309.87,161.51 B06.R1
BAC_07  (via drill 0.61)
  Top 0.254: v241.79,74.64 241.79,63.97 240.27,62.45 240.27,57.87 D11.E2
  Route2 0.254: v241.79,74.64 270.75,103.59 271.76,103.59 295.13,126.96 295.13,128.49 296.66,130.01 C07.D1 | B06.U1 312.41,152.36 312.41,149.31 300.72,137.63 300.72,134.58 300.21,134.07 C07.C1
  Bottom 0.254: C07.C1 299.71,133.57 297.17,131.03 C07.D1
BAC_07\  (via drill 0.61)
  Route15 0.254: v297.67,144.74 327.65,114.77 327.65,113.25 351.52,89.37 353.55,89.37 C03.U1
  Bottom 0.254: v297.67,144.74 298.18,144.23 306.31,144.23 307.83,145.76 307.83,148.81 309.36,148.81 B06.V1
BAC_08  (via drill 0.61)
  Top 0.254: v291.58,109.69 292.09,110.2 292.09,125.95 | 292.09,125.95 293.1,126.96 C07.E2 | v292.59,182.33 292.09,181.83 292.09,125.95
  Route2 0.254: v291.58,109.69 274.31,92.42 274.31,88.86 240.27,54.83 242.81,52.29 242.81,48.73 D11.J1 | v292.59,182.33 292.59,185.38 300.72,193.51 302.75,193.51 B06.D2
  Bottom 0.254: C07.F2 291.07,124.93 293.1,126.96 C07.E2
BAC_08\  (via drill 0.61)
  Route2 0.254: v351.01,157.95 353.05,155.92 341.36,144.23 341.36,142.71 337.81,139.15 v337.81,138.65
  Route15 0.254: v351.01,157.95 339.84,169.13 339.84,170.14 326.63,183.35 326.63,184.87 314.94,196.56 312.91,196.56 B06.C1 | v337.81,138.65 335.77,136.61 v340.85,131.53
  Bottom 0.254: v340.85,131.53 343.9,128.49 343.9,124.93 C03.F2
BAC_09  (via drill 0.61)
  Top 0.254: v315.45,171.67 316.98,170.14 316.98,159.47 v316.47,158.97 | v298.18,140.17 298.69,139.66 298.69,119.85 297.17,118.33 C07.J1
  Route2 0.254: v316.47,158.97 316.47,158.46 v298.18,140.17
  Route15 0.254: C07.J1 297.17,117.82 299.71,115.28 C07.K1 | v315.45,171.67 303.26,183.86 303.26,186.91 B06.F2
BAC_09\  (via drill 0.61)
  Route2 0.254: v353.05,125.95 352.03,124.93 352.03,123.41 351.01,122.39 350,122.39 348.98,121.37 348.98,120.36 346.95,118.33 344.92,118.33 C03.J2 | v289.04,171.67 289.55,171.67 304.28,186.4 304.28,188.94 305.8,190.46 B06.E2
  Route15 0.254: v353.05,125.95 353.05,126.45 349.49,130.01 349.49,135.09 v329.68,154.9 | v306.82,154.39 306.31,154.39 v289.04,171.67
  Bottom 0.254: v329.68,154.9 329.17,154.39 v306.82,154.39
BAC_10\  (via drill 0.61)
  Top 0.254: v254.49,241.77 253.99,242.28 253.99,254.98 250.94,258.03 250.94,262.09 249.41,263.61 A10.D2
  Route2 0.254: v338.31,107.66 342.38,111.72 343.9,111.72 C03.L2 | v277.86,159.98 278.88,159.98 301.23,182.33 303.77,182.33 305.8,184.37 B06.H2
  Route15 0.254: v254.49,241.77 272.78,223.48 272.78,222.47 291.58,203.67 291.58,202.15 298.69,195.03 298.69,194.02 304.28,188.43 304.28,186.91 306.31,184.87 B06.H2 | v328.66,108.67 327.14,108.67 305.8,130.01 305.8,131.03 282.94,153.89 282.94,154.9 v277.86,159.98
  Bottom 0.254: v338.31,107.66 337.81,107.15 330.19,107.15 v328.66,108.67
BAC_11\  (via drill 0.61)
  Top 0.254: v236.71,115.79 236.71,113.75 235.7,112.74 235.19,112.74 235.19,104.1 236.71,102.58 236.71,99.53 C11.R2
  Route2 0.254: v326.12,84.29 326.12,87.85 326.63,88.35 326.63,89.37 340.85,103.59 342.38,103.59 343.9,105.12 C03.N2 | v300.72,179.79 299.71,179.79 298.69,178.78 298.69,174.21 273.29,148.81 273.29,148.3 272.78,147.79 271.26,147.79 265.16,141.69 264.65,141.69 243.83,120.87 242.81,120.87 239.25,117.31 238.24,117.31 v236.71,115.79
  Route15 0.254: v249.41,83.78 236.71,96.48 236.71,98.51 C11.R2
  Bottom 0.254: v249.41,83.78 325.61,83.78 v326.12,84.29 | v300.72,179.79 304.28,179.79 305.8,178.27 B06.K2
BLK_IN_SYNC  (via drill 0.61)
  Top 0.254: v218.43,110.2 218.93,109.69 218.93,101.56 218.43,101.05 218.43,96.48 217.92,95.97 C13.S1
  Route2 0.254: v218.43,110.2 220.46,110.2 222.49,112.23 222.49,112.74 235.19,125.44 237.22,125.44 239.25,127.47 C11.E2
  Route15 0.254: v219.44,86.83 219.44,93.94 217.92,95.47 C13.S1
  Bottom 0.254: v219.44,86.83 218.93,87.34 145.78,87.34 145.78,96.99 144.77,96.99 144.77,101.56 CD18.AP2
BLK_IN_SYNC\  (via drill 0.61)
  Top 0.254: v216.9,78.19 215.89,79.21 215.89,97.5 214.87,98.51 C13.R1 | v136.64,212.31 139.18,209.77 139.18,119.34 136.64,116.8 v136.64,88.35
  Route2 0.254: v204.71,276.31 198.61,276.31 168.64,246.34 168.64,244.31 v136.64,212.31
  Route15 0.254: v216.9,78.19 246.87,48.22 248.91,48.22 D10.J2
  Bottom 0.254: v204.71,276.31 256.02,276.31 258.56,273.77 A10.A1 | v136.64,88.35 146.8,78.19 v216.9,78.19
BMB_00
  Bottom 0.254: C08.B1 284.47,137.63 284.97,138.14 308.85,138.14 309.36,137.63 C06.B1
BMB_00\
  Bottom 0.254: C06.A1 312.91,139.66 313.93,138.65 320.03,138.65 321.04,139.66 323.58,139.66 325.61,137.63 330.19,137.63 331.2,138.65 336.28,138.65 337.3,139.66 338.31,139.66 339.84,138.14 362.7,138.14 363.21,137.63 C02.B1
BMB_01
  Bottom 0.254: C08.H1 287.51,121.37 289.04,122.9 299.71,122.9 302.75,125.95 311.39,125.95 312.41,126.96 C06.E1
BMB_01\  (via drill 0.61)
  Top 0.254: v364.73,146.27 364.73,139.15 365.24,138.65 365.24,128.99 366.25,127.98 C02.E1
  Route2 0.254: v322.06,145.25 309.87,133.06 309.87,131.03 C06.D1
  Bottom 0.254: v322.06,145.25 323.07,146.27 v364.73,146.27
BMB_02  (via drill 0.61)
  Route2 0.254: v298.18,104.1 298.18,104.61 310.88,117.31 310.88,119.34 312.41,120.87 C06.H1
  Bottom 0.254: v298.18,104.1 284.97,104.1 284.47,104.61 C08.N1
BMB_02\  (via drill 0.61)
  Route15 0.254: v340.35,130.01 341.87,130.01 v350.5,121.37
  Bottom 0.254: v340.35,130.01 336.28,125.95 316.47,125.95 315.96,125.44 310.37,125.44 309.87,124.93 C06.F1 | v350.5,121.37 351.52,122.39 365.24,122.39 366.25,121.37 C02.H1
BMB_03  (via drill 0.61)
  Route15 0.254: v294.12,116.29 282.94,127.47 281.42,127.47 C08.E2
  Bottom 0.254: v294.12,116.29 311.39,116.29 312.41,115.28 C06.K1
BMB_03\  (via drill 0.61)
  Route15 0.254: v331.71,115.79 v338.31,109.18
  Bottom 0.254: v331.71,115.79 331.2,116.29 320.53,116.29 320.03,116.8 310.37,116.8 309.87,117.31 C06.J1 | v338.31,109.18 338.82,109.69 364.22,109.69 365.75,111.21 365.75,114.26 366.25,114.26 C02.K1
BMB_04  (via drill 0.61)
  Top 0.254: v277.86,107.15 277.86,111.21 C08.L2
  Bottom 0.254: v277.86,107.15 311.39,107.15 312.41,108.17 C06.M1
BMB_04\  (via drill 0.61)
  Route15 0.254: v328.66,103.09 327.65,104.1 321.55,104.1 320.53,105.12 318.5,105.12 315.96,107.66 314.44,107.66 313.93,108.17 313.93,109.18 311.9,111.21 309.87,111.21 C06.L1
  Bottom 0.254: v328.66,103.09 329.17,103.59 359.65,103.59 364.22,108.17 366.25,108.17 C02.M1
BMB_05
  Bottom 0.254: C08.S2 280.91,95.97 280.91,100.55 311.39,100.55 312.41,101.56 C06.P1
BMB_05\
  Bottom 0.254: C06.N1 309.87,104.61 310.88,103.59 313.93,103.59 316.98,100.55 365.24,100.55 366.25,101.56 C02.P1
BMB_06  (via drill 0.61)
  Route2 0.254: v296.66,113.75 296.66,114.26 304.79,122.39 305.8,122.39 312.41,128.99 v315.45,128.99 | v293.1,150.84 291.58,152.36 295.64,156.43 295.64,158.97 v302.75,166.08
  Route15 0.254: v296.66,113.75 312.41,98.01 312.41,95.97 C06.S1 | v315.45,128.99 293.61,150.84 v293.1,150.84 | v302.75,166.08 302.75,167.09 298.69,171.16 298.69,183.86 285.99,196.56 285.99,198.08 284.47,199.61 B08.B1
BMB_06\
  Bottom 0.254: C06.R1 309.87,98.51 310.88,97.5 355.59,97.5 358.63,94.45 365.24,94.45 366.25,95.47 C02.S1
BMB_07  (via drill 0.61)
  Top 0.254: v284.97,128.49 285.48,128.99 285.48,144.74 282.94,147.28 v282.94,184.37
  Route2 0.254: v281.93,123.91 281.93,125.44 v284.97,128.49
  Route15 0.254: v281.93,123.91 294.62,111.21 294.62,110.71 312.41,92.93 312.41,89.88 C06.U1
  Bottom 0.254: v282.94,184.37 282.94,190.46 287,190.46 B08.E1
BMB_07\
  Bottom 0.254: C06.V1 309.87,85.81 310.88,84.8 325.11,84.8 326.12,85.81 329.68,85.81 332.22,83.27 358.12,83.27 363.71,88.86 366.25,88.86 C02.U1
BMB_08  (via drill 0.61)
  Top 0.254: v281.93,154.39 282.43,154.9 282.43,180.81 279.89,183.35 279.89,189.95 280.4,190.46 B08.E2
  Route15 0.254: v281.93,154.39 281.93,153.89 302.75,133.06 302.75,131.03 C06.D2
BMB_08\  (via drill 0.61)
  Route15 0.254: v326.12,132.04 v335.26,122.9
  Bottom 0.254: v326.12,132.04 314.44,132.04 312.91,133.57 C06.C1 | v335.26,122.9 355.59,122.9 356.6,123.91 C02.F2
BMB_09  (via drill 0.61)
  Top 0.254: v289.04,149.82 288.53,150.33 288.53,167.6 287.51,168.62 287.51,171.16 B08.M1
  Route2 0.254: v285.48,146.27 v289.04,149.82
  Route15 0.254: v285.48,146.27 306.82,124.93 306.82,123.91 306.31,123.41 305.29,123.41 304.28,124.42 303.77,124.42 C06.F2
BMB_09\  (via drill 0.61)
  Route15 0.254: v315.96,115.79 307.32,124.42 307.32,125.44 306.31,126.45 306.31,126.96 C06.E2 | v357.11,114.26 357.11,117.31 C02.J2
  Bottom 0.254: v315.96,115.79 319.01,112.74 345.93,112.74 346.44,112.23 348.98,112.23 350,113.25 356.09,113.25 v357.11,114.26
BMB_10  (via drill 0.61)
  Top 0.254: v301.74,146.77 301.74,119.34 302.75,118.33 C06.J2
  Route15 0.254: v301.74,146.77 301.23,146.77 288.02,159.98 285.99,159.98 284.47,161.51 B08.R1
BMB_10\  (via drill 0.61)
  Route15 0.254: v324.09,119.85 325.61,119.85 v335.26,110.2
  Bottom 0.254: v324.09,119.85 307.83,119.85 306.82,120.87 C06.H2 | v335.26,110.2 352.03,110.2 353.55,111.72 356.6,111.72 C02.L2
BMB_11  (via drill 0.61)
  Route2 0.254: v286.5,130.52 301.74,145.76 302.25,145.76 309.36,152.87 v309.36,153.38
  Route15 0.254: v286.5,130.52 303.26,113.75 303.26,112.23 C06.L2 | v309.36,153.38 285.99,176.75 285.99,179.29 284.47,180.81 B08.J1
BMB_11\  (via drill 0.61)
  Route15 0.254: v315.45,103.59 306.31,112.74 306.31,114.26 C06.K2
  Bottom 0.254: v315.45,103.59 315.96,104.1 356.09,104.1 356.6,104.61 C02.N2
BMB_TO_DTB
  Top 0.254: 282.94,193.51 283.96,193.51 B08.D1 284.47,193.51 285.48,192.49 285.48,186.4 287,184.87 B08.H1 287,183.86 285.99,182.84 285.99,176.75 284.47,175.22 B08.L1 284.47,174.21 284.47,173.7 285.48,172.68 285.48,167.09 287,165.57 B08.P1 287,165.06 285.99,164.05 285.99,151.35 286.5,150.84 286.5,141.19 287,140.68 C08.A1 287.51,139.66 288.53,138.65 288.53,109.69 287.51,108.67 C08.M1 | 282.94,193.51 278.37,193.51 B08.D2 | 282.94,193.51 282.94,203.16 287,203.16 B08.A1
  Route2 0.254: C08.K2 280.91,115.28 280.91,118.83 282.43,120.36 282.43,122.39 283.96,123.91 C08.F1 | D12.L1 230.11,42.13 230.11,44.67 227.06,47.71 227.57,48.22 227.57,48.73 277.35,98.51 C08.R2 277.86,99.53 279.89,101.56 279.89,103.09 284.97,108.17 287,108.17 C08.M1
  Route15 0.254: C08.M1 287,108.67 284.97,108.67 282.94,110.71 282.94,112.23 280.91,114.26 C08.K2 | C08.D2 277.86,130.01 277.86,128.99 280.91,125.95 282.94,125.95 283.96,124.93 C08.F1
BMR00  (via drill 0.61)
  Route15 0.254: v170.17,166.08 167.12,169.13 162.04,169.13 144.77,186.4 140.7,186.4 108.19,218.91 108.19,220.94 85.84,243.29 85.84,249.39 85.33,249.9 85.33,255.49 83.3,257.52 81.27,257.52 A23.F1
  Bottom 0.254: v170.17,166.08 170.67,166.59 197.09,166.59 198.11,165.57 B14.P2
BMR00\  (via drill 0.61)
  Route15 0.254: v164.58,161 107.68,217.89 107.68,220.43 85.33,242.79 85.33,248.88 84.31,249.9 84.31,253.96 A23.H1
  Bottom 0.254: v164.58,161 165.09,160.49 194.04,160.49 195.06,161.51 B14.R2
BMR01  (via drill 0.61)
  Top 0.254: v101.58,271.74 86.34,271.74 85.84,271.23 85.84,270.73 81.27,270.73 A23.B1
  Route15 0.254: v101.58,271.74 118.86,271.74 163.05,227.55 164.07,227.55 199.63,191.99 199.63,189.45 201.15,187.92 B14.F1
BMR01\
  Route15 0.254: A23.A1 84.31,273.77 87.87,273.77 105.14,291.05 162.04,234.15 164.07,234.15 197.09,201.13 197.6,201.13 198.11,200.62 198.11,199.61 202.68,195.03 202.68,192.49 204.2,190.97 B14.E1
C00  (via drill 0.61)
  Top 0.254: A12.L2 223.51,244.31 221.98,242.79 221.98,191.48 225.03,188.43 225.03,163.54 224.01,162.52 B12.R2 | v219.44,99.02 219.44,120.36 218.93,120.87 218.93,156.93 217.92,157.95 217.92,158.46 B13.S1
  Route2 0.254: C15.E2 185.91,127.98 185.91,130.01 212.84,156.93 215.89,156.93 217.41,158.46 B13.S1
  Route15 0.254: A26.E2 37.07,261.07 37.07,264.63 46.72,274.28 46.72,275.3 63.48,292.06 164.58,292.06 184.39,272.25 196.58,272.25 223.51,245.33 A12.L2 | v219.44,99.02 219.95,99.02 254.49,64.48 258.56,64.48 D10.C1
  Bottom 0.254: B12.R2 223.51,161.51 221.47,159.47 217.92,159.47 B13.S1
C00\  (via drill 0.61)
  Top 0.254: v223,191.99 222.49,192.49 222.49,201.64 228.08,207.23 228.08,234.66 227.57,235.17 A12.P2
  Route2 0.254: v217.41,149.82 185.91,118.33 182.87,118.33 C15.J2 | B13.S2 211.31,159.47 211.31,161 213.85,163.54 215.38,163.54 216.9,165.06 B13.P1
  Route15 0.254: v217.41,149.82 217.41,152.36 B13.U1 217.41,152.87 217.41,154.9 215.38,156.93 212.84,156.93 211.31,158.46 B13.S2 | B15.H1 192.52,183.86 194.55,183.86 203.69,174.71 206.23,174.71 207.25,173.7 210.81,173.7 215.38,169.13 215.38,167.09 216.9,165.57 B13.P1
  Bottom 0.254: v223,191.99 202.17,191.99 195.06,184.87 192.52,184.87 B15.H1
C01  (via drill 0.61)
  Top 0.254: v254.49,198.59 254.49,181.83 255,181.32 B10.J1
  Route2 0.254: v230.62,153.89 235.19,158.46 235.19,162.52 253.48,180.81 255,180.81 B10.J1
  Route15 0.254: 230.11,153.89 232.65,151.35 234.68,151.35 236.21,149.82 B11.V2 | 230.11,153.89 229.6,154.39 228.59,154.39 222.49,160.49 220.97,160.49 218.93,162.52 215.89,162.52 214.87,163.54 213.85,163.54 212.33,165.06 211.31,165.06 B13.P2 | v230.62,153.89 230.11,153.89 | v177.28,276.31 179.31,276.31 184.39,271.23 185.91,271.23 213.35,243.8 213.85,243.8 | 213.85,243.8 216.9,243.8 217.41,243.29 225.03,243.29 226.55,241.77 A12.M2 | v254.49,198.59 254.49,199.1 235.19,218.4 235.19,222.97 217.92,240.25 217.41,240.25 213.85,243.8
  Bottom 0.254: v177.28,276.31 48.75,276.31 35.04,262.6 33.51,262.6 33.51,258.03 A26.F2
C01\  (via drill 0.61)
  Top 0.254: 209.79,164.05 208.27,162.52 B13.R2 | 209.79,164.05 209.79,170.14 210.81,171.16 B13.M2 211.31,172.17 212.33,173.19 v212.33,219.93 | v215.38,132.04 215.38,154.39 215.89,154.9 215.89,157.44 214.87,158.46 214.87,160.49 215.38,161 215.38,163.03 214.36,164.05 209.79,164.05 | v227.06,85.81 225.54,87.34 225.54,110.71 226.55,111.72 226.55,112.74 225.03,114.26 225.03,122.9 224.01,123.91 C12.F2
  Route2 0.254: v212.33,219.93 224.01,231.61 A12.R2
  Route15 0.254: v215.38,132.04 223,124.42 C12.F2 | v227.06,85.81 227.57,85.81 252.46,60.92 255,60.92 D10.D1
  Bottom 0.254: B10.P1 258.56,165.57 258.56,169.63 212.84,169.63 211.31,171.16 B13.M2
CK00  (via drill 0.61)
  Top 0.254: v147.31,216.37 145.78,217.89 145.78,234.15 144.77,235.17 A18.P2
  Route15 0.254: v147.31,216.37 168.64,195.03 168.64,193 202.68,158.97 204.2,158.97 B14.S1
CK00\  (via drill 0.61)
  Top 0.254: v196.07,178.27 196.58,177.76 196.58,156.93 195.57,155.92 B14.T2
  Route15 0.254: v196.07,178.27 195.57,178.27 155.43,218.4 155.43,220.43 141.72,234.15 141.72,238.21 A18.N2
  Bottom 0.254: B14.T2 195.57,155.41 197.09,153.89 203.19,153.89 204.2,152.87 B14.U1
CK01  (via drill 0.61)
  Top 0.254: v204.71,160.49 204.71,165.06 B14.P1 | v193.53,118.33 194.04,118.83 194.04,147.79 195.06,148.81 B14.V2
  Route2 0.254: v204.71,160.49 204.2,160.49 195.57,151.85 195.57,149.82 B14.V2 | v193.53,118.33 179.31,104.1 179.31,102.58 C16.P1
  Route15 0.254: C16.R1 176.77,99.02 179.31,101.56 C16.P1 178.8,102.07 176.26,104.61 C16.N1
CK01\  (via drill 0.61)
  Top 0.254: v174.23,125.95 174.23,96.99 173.21,95.97 C16.S2
  Route2 0.254: C16.S2 172.71,95.47 170.17,92.93 C16.T2 | v174.23,125.95 185.91,137.63 186.93,137.63 198.61,149.31 201.15,149.31 B14.V1
  Bottom 0.254: C16.T2 170.17,91.91 172.2,89.88 172.71,89.88 C16.U2
CLR_DF\  (via drill 0.61)
  Top 0.254: v177.28,34 174.23,34 174.23,91.91 171.18,94.96 171.18,107.66 168.64,110.2 v168.64,152.87 | v245.86,211.29 245.86,222.47 A11.U1
  Route2 0.254: v168.64,152.87 169.15,152.87 195.57,179.29 196.58,179.29 228.59,211.29 v229.09,211.29
  Bottom 0.254: v177.28,34 208.77,34 211.31,36.54 235.7,36.54 236.21,36.03 D11.N2 | v229.09,211.29 v245.86,211.29
CLR_DTF\
  Top 0.254: D11.U2 239.25,19.77 234.68,19.77 234.68,21.81 219.44,37.05 219.44,85.31 217.92,86.83 217.92,88.86 C13.U1
COMP+SH  (via drill 0.61)
  Top 0.254: v194.55,115.28 192.52,115.28 C15.K1 | 200.65,136.11 201.15,136.61 C14.B1 | 200.65,136.11 200.14,135.6 200.14,131.03 195.57,131.03 C14.D2 | v189.98,262.6 187.44,260.06 187.44,248.88 194.04,242.28 194.04,236.18 194.55,235.67 194.55,234.15 194.04,233.64 194.04,152.87 200.65,146.27 200.65,136.11
  Route2 0.254: v194.55,115.28 197.09,115.28 198.11,116.29 201.66,116.29 202.68,117.31 202.68,119.34 204.2,120.87 C14.H1
  Route15 0.254: C14.H1 204.2,121.37 202.68,121.37 197.09,126.96 197.09,127.98 195.06,130.01 C14.D2
  Bottom 0.254: v189.98,262.6 196.07,262.6 198.61,265.14 215.38,265.14 216.9,263.61 223.51,263.61 A12.D2
CSTA  (via drill 0.61)
  Route2 0.254: v271.26,123.41 270.75,123.41 249.41,102.07 248.4,102.07 246.87,100.55 241.29,100.55 231.63,90.89 226.05,90.89 225.03,89.88 225.03,85.81 222.49,83.27 222.49,77.69 177.28,32.47 173.21,32.47 D16.P2 | v325.11,118.83 327.65,118.83 329.68,120.87 330.19,120.87 336.28,126.96 336.28,127.98 338.31,130.01 C04.D1
  Bottom 0.254: v271.26,123.41 272.27,122.39 283.45,122.39 286.5,119.34 316.98,119.34 317.49,118.83 317.49,117.82 319.52,117.82 321.04,119.34 323.07,119.34 323.58,118.83 v325.11,118.83
CSTA\  (via drill 0.61)
  Route2 0.254: v384.54,179.79 361.68,156.93 361.68,151.85 343.9,134.07 341.87,134.07 C04.C1
  Route15 0.254: v384.54,179.79 384.54,181.32 386.57,183.35 386.57,200.62 357.62,229.58 356.09,229.58 v340.85,244.82
  Bottom 0.254: v340.85,244.82 338.82,246.85 253.99,246.85 252.46,245.33 249.41,245.33 A10.L2
DATA  (via drill 0.61)
  Top 0.254: v107.68,62.95 107.68,63.46 60.44,110.71 60.44,112.23 44.18,128.49 44.18,240.25 43.16,241.26 A26.M1
  Route2 0.254: C13.F1 213.85,123.91 213.85,122.9 213.35,122.39 209.28,122.39 208.27,121.37 208.27,120.36 200.14,112.23 200.14,107.66 192.52,100.04 192.52,98.51 181.34,87.34 181.34,84.8 142.73,46.19 142.73,45.17 140.19,42.63 140.19,40.6 141.21,39.59 142.73,41.11 142.73,43.14 144.26,44.67 CD18.BK2
  Bottom 0.254: v107.68,62.95 114.79,55.84 131.05,55.84 141.72,45.17 144.26,45.17 CD18.BK2
DATA\  (via drill 0.61)
  Top 0.254: v216.39,153.89 216.39,121.88 216.9,121.37 C13.H1
  Route2 0.254: v216.39,153.89 223.51,161 224.52,161 229.6,166.08 229.6,168.11 B12.N1
  Route15 0.254: v232.14,112.23 231.12,112.23 230.62,112.74 226.55,112.74 217.92,121.37 C13.H1
  Bottom 0.254: C16.D2 170.17,130.01 170.17,125.44 171.18,125.44 171.69,124.93 171.69,119.85 215.89,119.85 216.9,120.87 C13.H1 | v232.14,112.23 236.21,112.23 C11.L2
DB_00\  (via drill 0.61)
  Top 0.254: v372.86,72.1 377.94,77.18 377.94,103.59 380.99,106.64 380.99,124.42 v380.48,124.93
  Route2 0.254: v370.32,147.28 370.32,148.3 371.33,149.31 371.33,153.38 378.95,161 378.95,163.54 380.48,165.06 380.48,167.6 382.51,169.63 382.51,170.65 v383.02,171.16
  Route15 0.254: v380.48,124.93 380.48,126.45 384.03,130.01 384.03,133.57 v370.32,147.28 | v383.02,171.16 383.02,172.17 377.43,177.76 | 377.43,177.76 365.24,189.95 365.24,191.99 363.71,193.51 B02.D1 | 377.43,177.76 377.43,188.43 374.89,190.97 374.89,192.49 327.14,240.25 327.14,243.29 310.88,259.55 310.88,264.63 309.36,266.15 309.36,269.71 A06.B1
  Bottom 0.254: v372.86,72.1 309.87,72.1 309.87,67.53 D06.B1
DB_01\  (via drill 0.61)
  Top 0.254: 310.88,205.7 310.88,262.6 309.87,263.61 A06.D1 | 310.88,205.7 310.88,62.45 309.87,61.43 D06.D1 | v310.37,205.7 310.88,205.7
  Bottom 0.254: v310.37,205.7 310.88,206.21 374.38,206.21 374.38,196.05 370.82,192.49 368.29,192.49 367.27,191.48 B02.E1
DB_02\  (via drill 0.61)
  Top 0.254: 311.39,233.13 311.39,259.55 312.41,260.57 A06.E1 | 311.39,233.13 311.39,58.89 312.41,57.87 D06.E1 | v312.41,233.13 311.39,233.13
  Route15 0.254: v312.41,233.13 339.84,205.7 339.84,203.16 345.93,197.07 345.93,196.05 363.71,178.27 366.25,178.27 B02.K1
DB_03\  (via drill 0.61)
  Top 0.254: v374.89,119.85 v374.89,80.23
  Route2 0.254: v337.81,78.7 312.91,53.81 312.91,51.78 D06.H1 | v374.89,119.85 375.91,120.87 375.91,121.88 377.43,123.41 377.43,126.96 377.94,127.47 377.94,130.01 380.48,132.55 380.48,137.12 v383.02,139.66 | v373.37,188.43 373.37,187.41 365.24,179.29 365.24,177.25 363.71,175.73 B02.L1
  Route15 0.254: v383.02,139.66 383.02,151.85 386.06,154.9 367.78,173.19 365.24,173.19 363.71,174.71 B02.L1 | v373.37,188.43 371.33,190.46 371.33,195.03 326.12,240.25 324.6,240.25 312.91,251.93 312.91,253.96 A06.H1
  Bottom 0.254: v337.81,78.7 339.33,80.23 v374.89,80.23
DB_04\  (via drill 0.61)
  Top 0.254: 308.34,147.28 308.34,249.9 309.36,250.91 A06.J1 | 308.34,147.28 308.34,49.75 309.36,48.73 D06.J1 | v308.85,147.28 308.34,147.28
  Bottom 0.254: v308.85,147.28 309.36,147.79 336.28,147.79 336.28,163.03 337.3,164.05 362.19,164.05 363.21,163.03 B02.R1
DB_05\  (via drill 0.61)
  Top 0.254: v370.82,71.08 368.79,73.11 368.79,121.37 v369.81,122.39
  Route2 0.254: v369.81,122.39 374.38,126.96 374.38,133.06 v382,140.68
  Route15 0.254: v382,140.68 382,145.76 370.32,157.44 | 370.32,157.44 368.79,157.44 367.27,158.97 B02.S1 | v326.63,212.81 326.63,209.77 340.35,196.05 344.41,196.05 352.03,188.43 352.03,183.35 355.59,179.79 355.59,178.78 358.63,175.73 358.63,171.16 370.32,159.47 370.32,157.44
  Bottom 0.254: v370.82,71.08 371.33,71.08 371.33,66.51 367.27,62.45 356.09,62.45 350,56.35 321.04,56.35 311.39,46.7 309.87,46.7 309.87,42.13 D06.L1 | v326.63,212.81 326.63,230.59 316.98,240.25 309.87,240.25 309.87,244.31 A06.L1
DB_06\  (via drill 0.61)
  Top 0.254: v383.53,115.28 384.03,115.79 384.03,127.47 385.05,128.49 385.05,172.68 v383.02,174.71
  Route2 0.254: v383.53,115.28 383.02,115.28 375.4,107.66 375.4,107.15 340.85,72.61 340.35,72.61 326.63,58.89 326.63,56.86 318.5,48.73 318.5,48.22 312.91,42.63 312.91,39.08 D06.M1
  Route15 0.254: A06.M1 312.91,241.26 312.91,237.71 326.63,223.99 326.63,220.94 343.39,204.18 343.9,204.18 348.98,199.1 348.98,194.02 356.6,186.4 358.63,186.4 360.16,184.87 B02.H2
  Bottom 0.254: v383.02,174.71 380.99,176.75 371.84,176.75 364.22,184.37 360.67,184.37 B02.H2
DB_07\  (via drill 0.61)
  Top 0.254: 313.93,179.79 313.93,234.15 312.91,235.17 A06.P1 | 313.93,179.79 313.93,151.35 313.42,150.84 313.42,144.74 313.93,144.23 313.93,33.49 312.91,32.47 D06.P1 | v313.42,179.79 313.93,179.79
  Bottom 0.254: v313.42,179.79 313.93,179.29 328.66,179.29 329.17,179.79 355.59,179.79 356.6,180.81 B02.J2
DB_08\  (via drill 0.61)
  Top 0.254: v382.51,93.43 382,93.94 382,101.56 382.51,102.07 382.51,119.34 382,119.85 382,120.87 383.53,122.39 383.53,138.65 384.03,139.15 v384.03,167.6
  Route2 0.254: v382.51,93.43 380.48,91.4 380.48,88.35 347.97,55.84 347.97,54.83 326.63,33.49 326.63,31.46 315.45,20.28 312.91,22.82 312.91,25.36 D06.S1 | v354.06,174.21 358.12,170.14 357.11,169.13 B02.N2
  Route15 0.254: v354.06,174.21 342.88,185.38 342.88,186.91 333.23,196.56 333.23,201.13 318.5,215.86 317.49,215.86 316.98,216.37 316.98,220.43 315.96,221.45 315.96,223.48 312.91,226.53 312.91,228.56 A06.S1
  Bottom 0.254: v384.03,167.6 358.12,167.6 357.62,168.11 B02.N2
DB_09\  (via drill 0.61)
  Route2 0.254: v338.31,69.05 338.31,69.56 340.85,72.1 341.36,72.1 356.6,87.34 359.14,87.34 359.65,87.85 361.17,87.85 380.48,107.15 380.48,110.71 386.57,116.8 386.57,121.88 v385.56,122.9 | v366.25,186.91 366.25,186.4 359.14,179.29 359.14,167.09 360.16,166.08 B02.P2
  Route15 0.254: v366.25,186.91 355.59,197.57 355.59,199.61 326.63,228.56 326.63,230.09 304.79,251.93 304.79,258.03 303.26,259.55 303.26,263.61 A06.D2
  Bottom 0.254: v338.31,69.05 327.65,69.05 321.04,62.45 304.79,62.45 303.77,61.43 D06.D2 | v385.56,122.9 386.57,123.91 386.57,160.49 367.78,160.49 363.21,165.06 360.67,165.06 B02.P2
DB_10\  (via drill 0.61)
